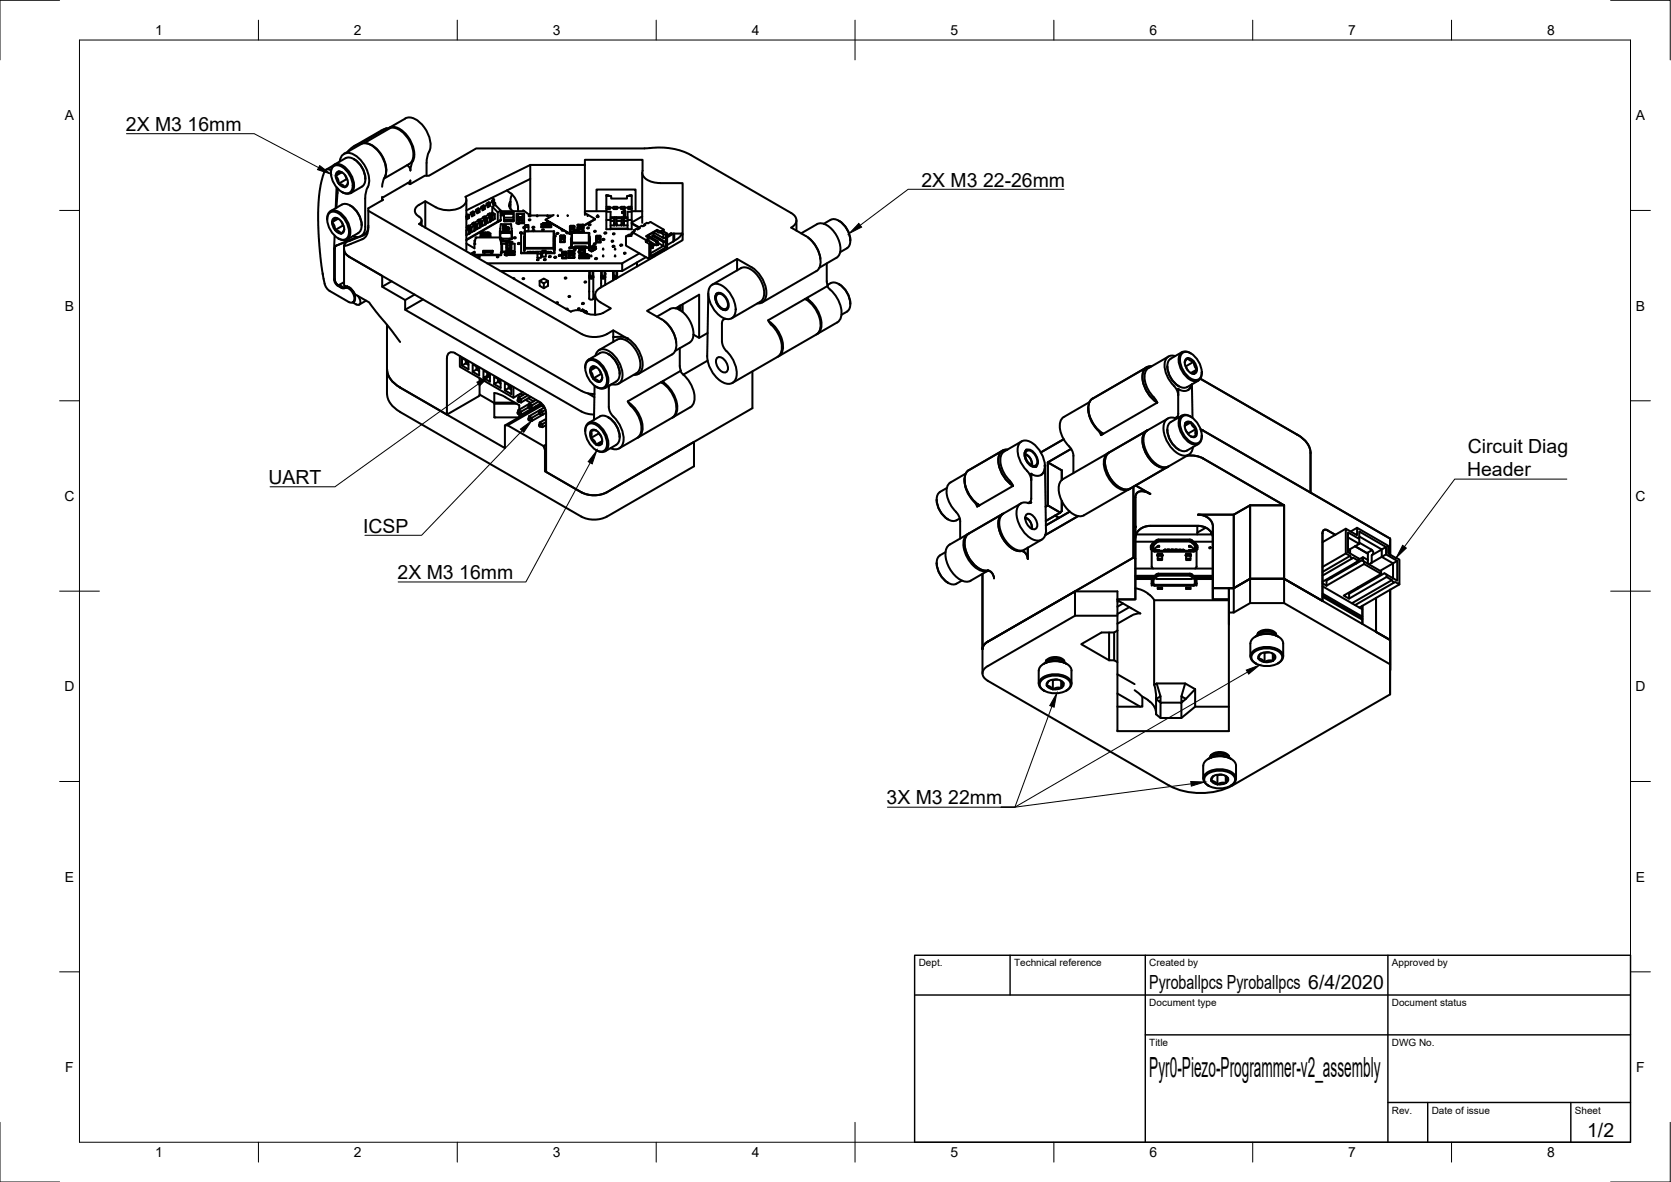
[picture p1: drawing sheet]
<svg xmlns="http://www.w3.org/2000/svg" width="420mm" height="297mm" viewBox="0 0 420 297" stroke-linecap="round" stroke-linejoin="round" font-family="sans-serif">
<defs><g id="words">
<text font-size="7" x="289" y="270.6">Pyr0-Piezo-Programmer-v2_assembly</text>
<g font-size="4.9">
<text x="31.7" y="32.9">2X M3 16mm</text>
<text x="231.7" y="46.9">2X M3 22-26mm</text>
<text x="369" y="113.9">Circuit Diag</text>
<text x="368.9" y="119.7">Header</text>
<text x="67.5" y="121.6">UART</text>
<text x="91.3" y="133.8">ICSP</text>
<text x="100" y="145.5">2X M3 16mm</text>
<text x="222.9" y="202.1">3X M3 22mm</text>
<text x="289" y="248.5">Pyroballpcs Pyroballpcs 6/4/2020</text>
<text x="399.1" y="285.7">1/2</text>
</g>
<g font-size="3.5">
<text x="39" y="8.8">1</text>
<text x="89" y="8.8">2</text>
<text x="139" y="8.8">3</text>
<text x="189" y="8.8">4</text>
<text x="239" y="8.8">5</text>
<text x="289" y="8.8">6</text>
<text x="339" y="8.8">7</text>
<text x="389" y="8.8">8</text>
<text x="16.3" y="30.2">A</text>
<text x="411.3" y="30.2">A</text>
<text x="16.3" y="78">B</text>
<text x="411.3" y="78">B</text>
<text x="16.2" y="125.9">C</text>
<text x="411.2" y="125.9">C</text>
<text x="16.2" y="173.7">D</text>
<text x="411.2" y="173.7">D</text>
<text x="16.3" y="221.6">E</text>
<text x="411.3" y="221.6">E</text>
<text x="16.4" y="269.4">F</text>
<text x="411.4" y="269.4">F</text>
<text x="39" y="290.8">1</text>
<text x="89" y="290.8">2</text>
<text x="139" y="290.8">3</text>
<text x="189" y="290.8">4</text>
<text x="239" y="290.8">5</text>
<text x="289" y="290.8">6</text>
<text x="339" y="290.8">7</text>
<text x="389" y="290.8">8</text>
</g>
<g font-size="2.5">
<text x="231" y="242.9">Dept.</text>
<text x="255" y="242.9">Technical reference</text>
<text x="289" y="242.9">Created by</text>
<text x="350" y="242.9">Approved by</text>
<text x="289" y="252.8">Document type</text>
<text x="350" y="252.8">Document status</text>
<text x="289" y="262.9">Title</text>
<text x="350" y="262.9">DWG No.</text>
<text x="350" y="279.9">Rev.</text>
<text x="360" y="279.9">Date of issue</text>
<text x="396" y="279.9">Sheet</text>
</g>
</g></defs>
<!-- layer: Visible -->
<g fill="none" stroke="#000" stroke-width=".51">
<path d="M86.9 39.8l-2.8 1.6M86.9 39.8a2.79 2.79 0 0 1 3.2 1 5.5 5.5 0 0 1 1.6 5.3l-.7 .8-2.8 1.6M88.9 40l.2 .1M89 36.7l7-4 1.2-.5-6.8 4-1.4 .5-1.6 1.5M90.7 36.2l-4.2 2.5M90.7 36.2a3.2 3.2 0 0 1 3.6 1 7.8 7.8 0 0 1 2.7 6.8l-.3 .6M91 36.1l-.6 .1M91.9 36a6.7 6.7 0 0 1 5.1 5.4l.1 1.9-.3 1.1M97.2 32.2l1-.1-6.7 3.9M97.7 32.2a3.1 3.1 0 0 1 3.7 .8 7.8 7.8 0 0 1 2.7 6.9l-.6 1.4-.3 1.6-.3-.9-.6-.5M98.2 32.1a5.3 5.3 0 0 1 4.9 3.6 5.1 5.1 0 0 1 .2 5.1l-.4 .4M101.9 29.8l-4.1 2.3"/>
<path d="M101.9 29.8a3.2 3.2 0 0 1 3.6 .9 7.8 7.8 0 0 1 2.6 6.8l-.7 1.9-.1 1.5M162.1 37.3h-42.4l-11.8 6.9h-1.1l-3.7 2.1-.6-.3M162.1 37.3h.3a19.1 19.1 0 0 1 11.3 1.7l25.2 14.5a1.93 1.93 0 0 1 1.4 1.9 1.93 1.93 0 0 1-1.4 1.8l3.7 2.1M82.3 55.1a1.82 1.82 0 0 1 .7-2 1.82 1.82 0 0 1 2.2 .2 5.7 5.7 0 0 1 2.6 6.3 1.71 1.71 0 0 1-2.6 .4M82.9 53.5a2.46 2.46 0 0 1 3.2 .9 5.1 5.1 0 0 1 1.4 5.1 1.87 1.87 0 0 1-3 0 5.4 5.4 0 0 1-1.9-5.6zM83.2 43.3v.2M83.2 43.3a1.78 1.78 0 0 1 .9-1.9 1.78 1.78 0 0 1 2 .2 5.7 5.7 0 0 1 2.6 6.3 1.9 1.9 0 0 1-2.8 .3M83.2 42.8l-.5-.2h-.7a11.2 11.2 0 0 0-1.7 5.8l-.3 5.1 .1 5.2 .4 5.7 .8 5.2a4.3 4.3 0 0 0 1.6 3.5l4.8 2.8M83.5 55.8a1.06 1.06 0 0 1 .8-1.1 1.06 1.06 0 0 1 1.2 .6 2.81 2.81 0 0 1 .8 3.1 1.34 1.34 0 0 1-2.1-.6M83.5 55.8l.1 .8 .6 1.2M83.8 41.6l-1.8 1.1M83.8 41.8a2.46 2.46 0 0 1 3.2 1 5.1 5.1 0 0 1 1.4 5.1 1.87 1.87 0 0 1-3-.1 5.4 5.4 0 0 1-1.9-5.6z"/>
<path d="M84.1 59.2l-.1 3.3M84.4 44.2a1.06 1.06 0 0 1 .8-1.1 1.06 1.06 0 0 1 1.2 .5 2.81 2.81 0 0 1 .9 3.1l-.6 .3M84.4 44.2l.1 .8 .7 1.2M84.6 47.1l-.2 5.2M84.7 48.4l.2 .1M84.9 47.4l-.3 4.8M85 55l-1.5 .8M85 59.9l.2 .1M85.1 55l-.3-.1a.49 .49 0 0 0-.5-.1 .49 .49 0 0 0-.3 .5l-.1 .1a.48 .48 0 0 0-.4 .4 .48 .48 0 0 0 .4 .5l.3 1.5M85.2 46.2l.9 .7 .6 .1M85.2 46.2l1 .3 .5 .5M85.4 40.6a2.2 2.2 0 0 1 1.3-2.1 2.2 2.2 0 0 1 2.4 .4 7.8 7.8 0 0 1 3.6 7.6l-.6 1.3-.2 1.5-.1 7.7"/>
<path d="M85.9 55.8l.5 1M85.9 43.3l-1.5 .9M86 51.4l-2.9 1.7M86 51.4a2.79 2.79 0 0 1 3.1 1.1 5.5 5.5 0 0 1 1.6 5.3l-.6 .8M86 43.4l-.8-.3-.4 .6a.48 .48 0 0 0-.3 .5 .48 .48 0 0 0 .3 .5l.4 1.5M86.2 56.7l-2 1.1M86.6 57.6l-.4 .7a.35 .35 0 0 1-.3 .4 .35 .35 0 0 1-.4-.3l-1.3-.6M86.8 44.1l.5 1M87.2 45l-2 1.2M87.5 46l-.8 1M88 51.6a5.8 5.8 0 0 1 2.9 5.1M89.1 40.1a6.1 6.1 0 0 1 2.8 4.9"/>
<path d="M89.9 59.6l-5.4 2.1-.3 .4v8.1l.1 .7a2.96 2.96 0 0 0 2 1.5l.4-.1M90.1 58.6l-2.9 1.6M91.8 57a2.16 2.16 0 0 1-.8 2.1 2.16 2.16 0 0 1-2.3 .2M92 58.6l-1.2 .8M92.6 53l53.7 31M96.1 50.1l.2 .1-3.7 2.2v4.9a2.85 2.85 0 0 1-1.5 2.8l-3.5 1.5-1.1 .2 .7-1.1 4.1-1.5a2.5 2.5 0 0 0 1.3-2.6M96.1 49.5v.9M96.7 44.6l-.5 1.3-.1 1M102.9 41.2l-6.3 3.7M103.2 46.3v-.9l-.2 .3-6.9 4M106 55.4v1.3M106.9 50.6v6.6"/>
<path d="M107.3 41v3.2M109.6 52.1l-2.7-1.5a3.6 3.6 0 0 0-2.6 2.1 2 2 0 0 0 1.4 2 .93 .93 0 0 1-.3 1.6l38.1 22a3.7 3.7 0 0 1 3.9 .4 5.9 5.9 0 0 0 6.2-1.2l-2.6-1.5M117.3 54.4v.1M117.3 57.2l.2-.1 .4 .3-.6 .5M117.3 50.3v12.5M117.3 57.9v1.2M117.4 56.9l.2 .2M117.5 57.1l.3-.4 .4 1v1M117.6 57.1h.1M117.6 53.9v.7l-.3 .2M117.6 54.6l.3 .2M117.9 56.8l.9-.5 .4 .3-.6 .5-.6-.2"/>
<path d="M117.9 58.7l-.6 .4M117.9 57.5v1.4M117.9 54.1v.7l-.6 .4v-.8M118.4 57.1v1.2M118.6 57.1v1.2M118.8 56.3l.3-.4 .2 .3 .3 .7v1M118.8 56.1l.1 .3M118.9 53.1v.8l-.3 .1M118.9 53.9l.4 .1M118.9 56.4h.1M119.2 56l.9-.5 .5 .4-.7 .5-.6-.2M119.2 58l-.6 .3h-.4"/>
<path d="M119.2 56.8v1.3M119.3 53.3v.7l-.7 .4v-.7M119.7 56.4v1.2M119.9 56.4v1.2M120.1 55.4l.2 .2M120.3 52.4v.7l-.3 .2M120.3 53.1l.3 .2M120.3 55.6h.1M120.5 55.3l.9-.6 .5 .4-.6 .5-.7-.2M120.6 57.2l-.7 .4-.3-.1M120.6 56l-.1 1.3M120.6 52.5v.8l-.6 .3v-.7"/>
<path d="M120.6 55.4l-.2-.2-.3 .3M120.6 55.4l.3 1M120.8 59.4h2.5M120.9 56.4v.7M121 55.6v1.2M121.2 58.7h-.4v.8h2.5v-.8h-.4M121.2 58.9l.4-.1v-.3l-.4-.1v.9M121.3 55.6v1.2M121.3 58.9v.4M121.4 54.6l.2 .2M121.4 54.7l.4-.3 .3 .5 .1 1.5M121.4 58.9h-.1"/>
<path d="M121.4 58.5h.2M121.4 58.9h.2M121.6 58.4h1v.5h-1zM121.6 58.9h1M121.6 54.8v.1M121.6 51.6v.7l-.3 .2M121.6 52.3l.3 .2M121.7 58.6v.1v-.1M121.7 58.7h.1M121.9 58.7h.2zM121.9 54.5l.8-.5 .5 .3-.6 .5-.7-.1M121.9 58.7h.2"/>
<path d="M121.9 58.7h.1M121.9 56.4l-.6 .4h-.4M121.9 55.2v1.4M122 58.6h.1M121.9 51.8v.7l-.6 .4v-.8M122 58.6l-.1 .1M122.1 58.7h.1M122.1 58.6h.2M122.2 58.6h-.1M122.2 58.6h.1M122.2 58.7h.1M122.3 58.7h.2"/>
<path d="M122.3 58.6h.1M122.4 54.8v1.3M122.4 58.6h-.1M122.4 58.6h.1M122.4 58.6v.1M122.4 58.7h-.1M122.4 58.7h.1M122.6 58.5h.1M122.6 58.9h.1M122.6 54.8v1.3M122.7 58.9l.2 .4v-.4h-1.6M122.7 53.8l.4-.2 .2 .3"/>
<path d="M122.7 53.8v.2M122.8 53.8l.1 .3M122.9 50.8v.8l-.3 .1M122.9 51.6l.3 .1M122.9 54.1h.1M122.9 58.9l-.3-.1v-.3l.3-.1v.9M123.2 53.7l.6-.3 .6 .4-.5 .3-.6-.2M123.2 55.7l-.6 .4-.4-.1M123.2 54.4v1.4M123.2 51v.7l-.6 .4v-.7M123.3 53.9l.3 1M123.5 54.9v.7"/>
<path d="M123.6 49.7l.6 .4-.5 .3 .3 .2-.8 .4-.3-.2-.6 .4 .3 .2-.7 .4-.3-.2-.6 .4 .3 .1-.7 .4-.3-.1-.7 .3 .4 .2-.7 .4-.4-.2-.6 .4 .3 .2-.7 .4-.3-.2-.3 .2M123.7 54.1v1.2M123.8 51.9v1.5M123.9 54.1v1.2M124 50.6v.7l.5-.3-.3-.2-.2 .2M124.2 50.1v.7M124.4 53.8v1.2l-.5 .3-.4-.1M124.5 51v.5M125.1 55.8h.1M125.1 55.7l-7.8 4.5M125.2 53.3l.7-.4v2.5l-.7 .4zM125.7 55.5l-8.4 4.9"/>
<path d="M125.8 59.9h.1M125.8 59.9h2.9M125.8 58l-.1 1.7M125.8 57.5h.1M125.9 53.6l.1 .3zM125.9 52.9l-1.4-1.4-.7 .4 1.4 1.4M125.9 53.1h5.9M125.9 54h.5M125.9 53.6h.2M126 58.3h2.4v.2h-2.4zM126 58.5h2.4M126.1 53.3h.3v.9h-.5"/>
<path d="M126.1 53.1v.8M126.3 60v.7h1.8v-.3h-1.8M126.6 57.5h.2M126.6 57.7h.4v.1l-.2 .1zM126.6 57.4h.4v.1zM126.6 57.3h.4zM126.6 57.1h.4zM126.6 56.9l.4-.1-.1 .1 .1 .1zM126.6 56.7l.4 .1zM126.6 56.8h.4M126.6 58.2h.4M126.6 56.9l.4 .1"/>
<path d="M126.6 58.1v.1M126.7 57.5h.3M126.7 58h.3v.1h-.4zM126.7 57.5h.1M126.7 57.1h.1zM126.7 56.7h.1zM126.7 56.7h.1M126.7 57.3h.1M126.7 56.9h.2zM126.7 53.7h2.4v1h-2.4zM126.7 55.3v.2h.4M126.7 54.7v.6"/>
<path d="M126.7 55.5v.1M126.7 55.3h.3M126.7 57.2h.1M126.8 53.7v-.3h2.4v2.2h-2.4v-.1h2.4M126.8 55.5h.3M126.8 57.7l-.2 .2 .4-.1M126.8 57.7l.2 .1M126.9 56.7h.1zM126.9 56.7h.1M126.9 57.1h.1M126.9 57.6h.1M126.9 56.9h-.2"/>
<path d="M127 55.3l-.2 .1M127 58.1h-.3M127 57.3h-.4M127 56.8l-.1 .1M127 58.1v.1M127.1 55.5v.1M127.1 55.4h.4M127.5 57.6h.3M127.5 55.5h.3zM127.5 55.5h.9v.1M127.5 55.5v.1M127.5 57.3h.4h-.3"/>
<path d="M127.5 57.3l.3 .1-.3 .1h.4M127.5 57.1l.4 .1zM127.5 57.3l.3 .1M127.5 57.6h.4M127.5 47.8l.9 .8M127.5 57.6h.1M127.6 57.6h-.1M127.6 57.3l.3 .1-.3 .1h.3M127.6 55.3h.6M127.6 55.3l.2 .1M127.9 57.6h.1M127.9 57.3h-.3"/>
<path d="M127.9 57.5h.1M128.1 60v.4M128.3 55.3l-.2 .2h.3M128.3 50.7v.3M128.3 50.7a1.54 1.54 0 0 0 .7 2.4M128.4 51.5l-.4 .3M128.4 50.7h-.1M128.4 48.5a5.3 5.3 0 0 1 1.9 4.6M128.4 55.4h.4M128.5 56.4l.1 3.7M128.5 56.4h-2.6l-.1 3.7M128.6 58v2"/>
<path d="M128.6 59.9h.1M128.7 57.5h.1M128.7 55.5h.4zM128.7 55.5h.4M128.7 55.5v.1M128.8 48.9l-.4 1v2.6M128.9 55.3h.2M128.9 55.3l.2 .1M129.1 55.3v.3M129.1 54.7v.6M129.3 59.6l.4 .1-.4 .2zM129.9 56v-2.3h1.9v2.4h-1.9v-.1h1.9"/>
<path d="M130.2 56.1l.2 .2 .2-.2M130.3 55v.5v-.4h1v.2h-.3M130.3 54.5h1.1v-.8h-1.1v1.3h1.1v-.5M130.3 55.3h.3M130.6 55.3v.3M130.6 55.2h.4M130.8 58.4l.5 .1-.5 .1zM131 55.3v.3M131.4 55.5l-.1-.2v.3M131.4 55v.3M131.8 58.7h-.8v5h4.1M131.8 59.5v.4"/>
<path d="M131.8 60v.4M132 56.5h.9v1.6h-.9zM132 57.1h.9M132 57.1l-.5 .1 .5 .1M132 58.1h7.2M133 55.1l.4 .1-.4 .1zM133.3 45v9.2l-1.8-1.4v.3M133.3 41.5v3.5l-16 7.9M133.4 54.1l-.2 .3-.3-.2 .2-.1 5.9 .1M133.9 57l.5 .1-.5 .1zM134 57.8l.4 .1-.4 .1zM135 54.4l.1-.3 .1 .3"/>
<path d="M136.4 57.6l.4 .1-.4 .1zM136.5 56.5h.2l-.1 .4v-.3h1.6M136.5 56.9v-.8h.4v.3h-.2l.2 .2 1.1-.1-.2-.4h.4v.8M136.5 56.3h-.4v.7M136.7 56.1h.2M136.9 56.1h.9v.4h-.9zM136.9 56.2h.1M136.9 56.3h.2M137 56.2l-.1 .1M137 56.3h.1M137.1 56.3h-.2M137.1 56.2l-.2 .1"/>
<path d="M137.1 56.2l-.1 .1M137.1 56.2h-.2M137.1 56.3h.2M137.1 56.3h.1M137.2 56.2l.1 .1M137.2 56.2v.1M137.3 56.3h.1M137.4 56.2h.1M137.4 56.2h.2l-.2 .2zM137.4 56.3h.1M137.6 56.2l-.2 .2M137.6 54.4l.1-.3 .1 .3"/>
<path d="M137.6 56.3h.2M137.6 56.3h.1M137.6 56.2l.2 .1M137.6 56.2v.1M137.8 56.3h.1M137.8 56.1h.2M138.2 56.6v.3M138.2 56.3h.4v.8h-2.5l2.5-.1M138.2 56.5h-.2l.2 .1M139.2 58.1l.1 .1v4.3l-.1-.2zM139.2 54l-2 1.3 6.1 3.5-6.1-3.6M139.3 58.7l.1 5h-2.2"/>
<path d="M139.3 60v.4zM139.3 59.5v.4zM139.4 59.2l.4 .1-.4 .2M140.1 58.6h.3l-.3 .1zM140.2 54.3l.1-.2v.2M141 59.4h.8v.5h-.8zM141 59.9l.2 .1M141 59.4l-.2-.1v1.4M141 59.3h.2M141 60h.1M141.3 59.7h.3M141.3 59.4h.3"/>
<path d="M141.3 59.4h.3zM141.3 59.7h.3zM141.3 59.9h.1M141.3 59.6h.3M141.3 59.7h.1M141.3 59.4h.2M141.3 59.7h.2M141.3 59.8h.3M141.3 59.4l.2 .1zM141.3 59.5l.3 .1zM141.3 59.6h.1M141.4 59.5l.1 .1z"/>
<path d="M141.4 59.5l.1 .1M141.4 57.7l-.1 .3 .4-.1M141.4 59.5h.1M141.4 59.8h.1M141.5 59.8h.1M141.5 59.8l-.2 .1M141.6 59.7h.1M141.7 59.3h.1M141.8 59.3v-.2h-.8l.2 .3 .8-.1v1.6h-1.2v-.2h1.2M141.8 59.9l-.1 .1M141.8 59.3v.1M141.8 60h.1"/>
<path d="M142 59.6v.2M142.6 58.4l-.2 .2 .4-.1M142.7 54.2v-.1l.1 .1M143.5 56.9v-.2h.8l-.2 .3-.8-.1v1.4h1.2l-.8 .3M143.5 57.6l.8 .1v.4M143.5 57.6l.6-.1 .2 .2M143.5 57h.8v.5h-.8zM143.5 57.5l.1 .1M143.5 56.9v.1M143.5 57.6h.1M143.5 57.7v.4M143.5 56.9h.1"/>
<path d="M143.7 60v1.8M143.7 58.6l-.4 .2M143.7 58.6v3.7h.9M143.7 57l.1 .1M143.7 57.2h.4M143.7 57.4h.4M143.7 57.4h.4zM143.7 57.2l.3 .1zM143.7 57.1l.4 .1zM143.7 57l.3 .1M143.7 57.3l.3 .1M143.8 57l.2 .1"/>
<path d="M143.8 57.4l.2 .1zM143.8 57.1l.2 .1zM143.8 57v.1M143.8 57.3h.2zM143.8 58.5v2.5M143.8 57.3h.2M143.8 57.1h.1M144 57.4h.1M144 57.4h-.2M144 57.1v.1M144 57.1l-.2 .1M144 57.3v.1"/>
<path d="M144 57.3h.1M144.1 56.9h.4v1.4M144.3 57.5l-.2 .1M144.3 57.6h.1M144.3 58.1l-1 .6M145.2 58.2h1.5v.1h-1.5zM145.2 57.3v.9M145.2 57.7l-.7 .4M145.2 57.6l-.9 .5M145.2 57.2h.3M145.3 57.2l-.1 .1M145.5 57.2v.1"/>
<path d="M145.5 56.5h.9v.4h-.9zM145.5 57.2h.9v.5h-.9zM145.5 57.7v.6h.9v-.6M145.5 56.9v.3M145.5 56.5h-.3v.8M146.4 56.5h.3M146.4 56.9l.1 .3M146.5 57.2h.2M146.7 57.2v.1M146.7 56.5v.8M146.7 57.3v.9M147.1 53.5l2.5 1.6-2.9 1.7"/>
<path d="M147.1 53.1h5.4M147.1 41.5v12.5M147.7 54.2l.1-.2v.2M147.7 57.2l.4 .1-.4 .1zM148 58.5v2.5l.2 .2v-2.6h-4.5M148.1 56.4l.4 .1-.4 .1zM148.2 60v.3zM148.2 59.5v.5M149.5 58l.3 .1-.3 .1zM149.6 55l-2.9 1.7M150 53.1v-5.5h9.8v5.5M150.1 59.5h.8v.5h-.8z"/>
<path d="M150.1 59.5l-.2-.1v1.4M150.1 59.4h.1M150.2 54.3l-.2 .1 .2 .2 .3-.1-.1-.2M150.3 59.5h.3M150.3 59.5h.3zM150.3 59.7h.3M150.3 59.8h.3zM150.3 60h.1M150.3 59.5h.1M150.3 59.7h.1M150.3 59.9l.3 .1h-.3M150.4 59.7h.1"/>
<path d="M150.4 59.6l.1 .1zM150.4 54.5l-.1-.5-.2 .6M150.5 59.6h.1M150.5 59.9h.1M150.5 59.9l-.2 .1M150.6 59.8h-.3h.3M150.6 59.5h.1M150.6 59.7h.1M150.7 59.4h.2M150.9 59.4v-.2h-.8l.1 .3 .8-.1v1.5h-1.1l1.1-.1M150.9 59.4v.1M152 58.4l.5 .1-.5 .2z"/>
<path d="M152.5 53.2v4.4h5.3M152.5 49.2h1.2v.7h3.9v-.7h1.2v2.8h-.9v.2M152.5 52h.9v.2M152.5 55.3h1M152.5 52.3h.9M153.3 49.2l-.8-.2v3.5M153.5 57.4h4.3M153.5 54.9h1M153.5 54.6h4.3M153.5 55.5h.9M154.2 58.7l.4 .1-.4 .1zM154.3 52.2v-.2h.9v.2"/>
<path d="M154.3 52.3h.9M154.5 56.2l-.1 .4h-.9M154.5 55.1l-.1 1.5M154.5 54.6v2.1M155 54.6v2.1M155 54.9h1.4M155 55.2v.3M156.1 52.2v-.2h.9v.2M156.1 52.3h.9M156.3 55.5v1.1M156.4 55.2l-.1 .3h-1.3v1.1v-.3M156.4 56.3l-.1 .3h-1.3"/>
<path d="M156.4 54.6v2.1M156.4 53.3l.8-.4v1.5h-.4l.1-1-.5 .2zM156.8 55.1l.1 .4h.9M156.8 54.6v2.1M156.8 54.9h1M156.9 55.5v1.1l-.1-.4M156.9 56.6h.9M156.9 52.9l-.5 .4M156.9 52.9h.3M157.8 55.3h1M157.9 52.2h-.9v.3h-.9v-.3h-.9v.3h-.9v-.3h-.9v.3h-.9v.7h1v4.4M157.9 52.2v.3h.9v.7h-1v4.4h1v-4.4"/>
<path d="M157.9 52.3h.9M158 49.2l.4-.2h.4v.2M158.8 58.9l-.7 .1-.7 .4M158.8 56.1l2.2 1.2-1.6 .6M158.8 53.1h2.7M158.8 52v.5M158.8 56.2l1.9 1M159 58.4l-.2 .2v.7l-1.4 .1v2.3l5.8 3.4v-3.8M159.3 58.2l-.3 .1v.4l-.2-.1M159.4 57.9v.3M161.5 54.4l-2.7 1.5M161.5 43.4v12.6"/>
<path d="M161.6 42.9v-2.7h-14.5v1.3h-13.8l-16.2 8a1.98 1.98 0 0 1-1.3 2.7 7.1 7.1 0 0 1-6.2-.1M161.6 42.9a2.61 2.61 0 0 0 2.5 2.9l1.9 .2h5.6v14.4l-20.6 11.9a1.93 1.93 0 0 0-1.4 1.8 1.93 1.93 0 0 0 1.4 1.9M162 56.4l.3 .1-.7 .4-.2-.2-.7 .4v.3M162 56.7v-.3l.6-.4 .3 .1 .7-.3 3.3 1.9v.5l.8 .5v3.8l-.7 .4M162.9 59.6l.3-.2 2.2 1.2M162.9 59.5l2.1 1.3M163.2 59.8l-.2 .6M164.3 59.1l3.1 1.7h-.6l-2.8-1.5M164.9 58l.8 .5 .3-.2M165.2 57.7l-2.7 1.7M166 58.2v.1l.2-.1v.4M166.8 58.9v.9l-2.5-1.4v.7l-.3 .2v.5"/>
<path d="M166.8 59.8h.6v2.4l-3.8 2.2v-3.3l.4 .2M166.9 57.7l-.9 .5-.8-.5-2.8 1.7 .8 .4-.8 .5-3.4-1.9 .7-.4-.3-.1M166.9 58.2l-.7 .4 .6 .3 .9-.2M167.4 58.9v.9M168.8 58.6l-1.1 .6M169.3 58.7l-1.6 1M169.4 58.7l-.1 2M169.5 58.7v1.8l-.2 .2M171.4 58.8l-.5 .7-1.4 1M171.5 58.8l.1 .2M171.5 58.7h-.1M171.6 58.7h-2.8l-1.1 .6"/>
<path d="M200.3 55.4v2.6M201.4 58.6l4-2.3a3.3 3.3 0 0 1 3.8 1.3 6.6 6.6 0 0 1 1.9 6.3l-.8 .9M202.6 59.3a7.8 7.8 0 0 1 3.6 7.6l-.5 .9-.5 .4-13.6 7.8M203.1 59.7a7.8 7.8 0 0 1 3.2 5.4M207.1 56.2l1.7-.9a2.79 2.79 0 0 1 3.2 1 5.5 5.5 0 0 1 1.6 5.3l-.6 .8-1.8 1M210.9 55.5h.2M211.1 55.5a6.1 6.1 0 0 1 2.7 5M81.1 68.7l.1 .3M84 62.6v7.7M84 70.3l.2 .7 .7 .8M84 62.5h.1M84.9 71.8l1.2 .7 .5-.1"/>
<path d="M85.3 71.6l1 .6M86.5 70.9l-1.3 .7M86.5 62.7a2.17 2.17 0 0 0 1.3 1.8M86.5 61.7v9.7l.2 .6h.4a2.75 2.75 0 0 1 2.1 1.9l3.6 2.1 7.8 9.9M86.6 72.4a2.35 2.35 0 0 1 2.5 2.6 .9 .9 0 0 1-.4 1 .9 .9 0 0 1-1-.1M86.8 72.3a2.38 2.38 0 0 1 2.5 2.6l-.4 1 .2-.1-.4 .2 1.2 .6a.96 .96 0 0 0 .5-1.6l-.5-.7M86.9 72h.1M87.3 72l-.7 .4M92.1 75.6l-1.8 1M98.5 70.7l-2.4 1.4M104.2 74l-2.3 1.4M106.4 75.3l-4.5 2.5"/>
<path d="M117.3 61.2l2 1.2M118.4 63.9l.9-.5v.6M118.9 63.6l-.3 .2M119.3 63.5h.1M119.3 62.4l.3-2.7h6.1l.3 1.6v2.7M119.3 64h6.7v.1h-6.7zM119.3 63.2l-1 .6M119.5 60.5h-.2v.7M120.3 64.5l.4 .1-.4 .1zM121.5 63h2.4v.3l-.4 .2h-1.7l-.3-.2zM121.5 63.3v.3M121.8 63.5v.3"/>
<path d="M122.5 66.2h33.9v1.9h-30.6M123.5 63.5v.3M123.9 63.3v.3M125 64.4l.3 .1-.3 .1zM125.8 60l.5 .1M125.9 60.5h.1v.7M126.3 63.2h1M126.9 64h2.5M127.2 64.1l.2 .1 .2-.1M127.3 63.3h-.4v.8h2.5v-.8M127.3 63.5l.4-.1v-.3l-.4-.1v.9M127.4 62.1v.7h.3v-.2"/>
<path d="M127.4 62.1h.2M127.4 63.6v.3M127.4 61.1l-.4 .2M127.4 61.3v.1M127.5 63.1h.2M127.6 62.6l-.2 .1M127.6 62.2l-.1 .1M127.6 61.3l-.1 .1M127.6 61.7l-.1 .1M127.6 61.3h-1.3v2h.6M127.6 61.7v-.9h.7v1.8h-.7h.7M127.6 62.3h-.2v.2h.2"/>
<path d="M127.6 62.6h-.2v.1h.3M127.6 61.8h-.2v.3v-.2M127.6 61.2h-.2v.6M127.6 60.9h-.2v.3v-.2M127.6 61.4h-.2v.3h.2M127.6 61.7l-.2 .1M127.6 62.2l-.2 .1M127.6 61.7v.9M127.7 63.5h1.1l.1 .4v-.3h-1.5M127.7 63h1v.5h-1zM127.7 63.5l-.3 .1M127.7 62.7h.1"/>
<path d="M127.8 63.2v.2l.1-.1-.1-.1M128 63.3l.1-.1v.2zM128.1 63.2h.1M128.1 63.4h.1M128.1 63.2l-.1 .1M128.2 62.7h.1M128.3 63.2l-.1 .1M128.3 63.2l.1 .1M128.3 61.3h1.1v2M128.3 61.8h.2v.3M128.3 62.3h.2v.2h-.2M128.3 62.6h.2v.1h-.3"/>
<path d="M128.3 61.4h.2v.3h-.2M128.3 61.7l.2 .1M128.3 60.9h.2v.9M128.3 62.2l.2 .1M128.4 62.2v.1M128.4 62.6l.1 .1M128.4 61.7v.1M128.4 61.3v.1M128.4 60.9l.1-.1 .4 .1-.3 .1M128.4 63.3h-.4M128.4 63.3l.2-.1-.1 .1M128.4 63.4h.2"/>
<path d="M128.5 61.3v.1M128.5 63.2h-.1M128.5 63.2v.1M128.5 63.2l-.1 .1M128.5 63.3l-.1 .1M128.5 61.9v.2h-.2M128.5 62.1v.7h-.3v-.2M128.5 61v.2h-.2M128.6 60l-.5 .1M128.7 63.1h.1M128.9 69.9h.4v.2M129 63.5l-.3-.1v-.3l.3-.1v.9"/>
<path d="M129 63.3h.4M129 63.2h.4M130.3 61.1l.4 .1-.4 .1zM131 63.5h4.1M131.4 69.9l.4 .1-.4 .1zM131.8 62.2v.8M131.8 60.4v.4M131.8 60.8v.4M131.8 61.3v.4M131.8 61.7v.4M132 62.3v-4.2l-.2 .1v5.3M132.7 63.4v.1"/>
<path d="M133.2 63.4h-.5l.5 .1M133.5 63.4v.1M133.9 63.4h-.4l.4 .1M134.2 63.4v.1M134.7 63.4h-.5l.5 .1M135 63.4v.1M135.1 65.2l.4 .1-.4 .1zM135.1 63.3h.9v1.5h-.9zM135.1 63.4h-.1h.1M135.1 63.8h.9M135.7 70.6l1-.6 1.1 .6-1.1 .6zM135.7 70.6v1.2l1 .6 1.1-.6v-1.2"/>
<path d="M136 63.5h.4M136 63.7h.4M136.2 63.4h-.2l.2 .1M136.4 63.5h.8v1h-.8v-1.5h.8v.5M136.7 71.2v1.2M136.8 65.1l.5 .1-.5 .1zM137.2 63.5h2.2M137.7 63.4h-.5l.5 .1M138 63.4v.1M138.1 64.4l.4 .1-.4 .1zM138.5 63.4h-.5l.5 .1M139.2 62.3h-7.2l-.2 .2h7.5v1"/>
<path d="M139.3 62.2v.3zM139.3 61.7v.4zM139.3 61.3v.4zM139.3 60.8v.4zM139.3 60.4v.4zM139.3 62.6v.4zM139.4 64.5l.5 .1-.5 .2zM139.9 76l.4 .1-.4 .1zM140.6 64.1l.4 .1-.4 .1zM140.8 62.7l.4 .1-.4 .1zM141 60.5v-.4h.8v.4M141 60.1l.2-.2h.5l.1 .2"/>
<path d="M141.5 63.4v-.2h.8l-.1 .2h-.9v1.4h1.2v.1h-1.2v-.1M141.5 64.1l.8 .1v.4M141.5 64.1l.7-.1 .1 .2M141.5 63.4h.8v.6h-.8zM141.5 64l.1 .1M141.5 63.4h.1M141.5 64.1h.1M141.5 64.2v.4M141.8 63.9h.3M141.8 63.9h.3zM141.8 63.7l.3 .1zM141.8 63.6l.3 .1z"/>
<path d="M141.8 63.5h.1M141.8 63.8h.2M141.8 63.7v.1M141.8 63.9h.1M141.8 63.9h.2zM141.8 63.6l.2 .1zM141.8 63.8h.2zM141.9 63.5h-.1M141.9 63.5v.1M141.9 63.5l.2 .1zM141.9 63.5l.2 .1M141.9 63.8h.2"/>
<path d="M142 63.6l-.2 .1M142 63.9h.1M142 63.9h-.2M142.1 69.8l.3 .1-.3 .1zM142.1 63.9h.1M142.2 63.4h.3v1.4M142.3 64l-.1 .1M142.3 64.1h.1M142.4 77.6h.3l-.1 .2M142.9 64.7h1.5v.1h-1.5zM142.9 63v.8M142.9 63.8v.9"/>
<path d="M143 63h.2M143 63h-.1M143 63.7l-.1 .1M143 74.4l.4 .1-.4 .1zM143.2 62.2h.4l-.4 .1zM143.2 63h.1M143.2 63h.9v.5h-.9zM143.2 63.7h.9v.5h-.9zM143.2 63.5l.1 .3-.3-.1M143.2 64.2v.6h.9v-.6M143.7 62.2h.9M143.7 60l-.2 .2 .2 .1"/>
<path d="M144.1 63.5v.2M144.2 63.7h.2M144.2 63h.2M144.2 63.7l-.1 .1M144.3 62.6l.5 .1-.5 .1zM144.4 63v.8M144.4 63.7l.1 .1M144.4 63.8v.9M144.4 64.7h.1M144.6 62h.4v.3h-.4v-.3h.4M145 62.3h.3M145 62.2h.3"/>
<path d="M145.3 62h.5v.3h-.5v-.3h.5M145.4 77.5l.4 .1-.4 .1zM145.6 63.4h1.5v.1h-1.5zM145.6 63.4h.1M145.6 63.1l-.2 .2 .2 .1M145.6 62.4v1M145.8 62.3h.3M145.8 62.2h.3M145.9 62.4l-.3 .1M145.9 62.4h.9v.5h-.9zM145.9 62.9v.6h.9v-.6M146 64.3h.2l-.1 .4v-.3h1.6"/>
<path d="M146 63.8l.4 .1v.3h-.2l.2 .2 1.1-.1-.1-.4 .3-.1v.9M146 63.8v.9M146 64.1h-.4v.7M146 63.9l-.1 .2M146.1 62h.4v.3h-.4v-.3h.4M146.2 63.9h.2M146.3 78.1l.4-.2 .6 .4-.3 .2 .5-.1M146.4 63.8h1v.5h-1zM146.4 76.1l.5 .2-.5 .1zM146.4 64h.1M146.4 64h.2l-.2 .1M146.4 64.1h.2"/>
<path d="M146.5 77.8h.1M146.5 62.3h.3M146.5 62.2h.3M146.6 64.1h-.2M146.6 64l-.1 .1M146.6 64l-.1 .1h.1M146.6 64h-.2M146.7 64.1h.2M146.7 64.1h.1M146.7 77.9l-.2-.1-.5 .3M146.7 77.9h.1M146.7 64l.1 .1"/>
<path d="M146.7 64v.1M146.8 62h.5v.3h-.5v-.3h.5M146.8 62.4l.3 .1v.9M146.9 64.1h.1M146.9 64v.1M146.9 64h.2l-.2 .2zM147 64.1h.1M147 70.8l.4 .1-.4 .1zM147.1 64l-.2 .2M147.1 62.4v.1M147.1 64.1h.2M147.1 64.1h.1"/>
<path d="M147.2 64l.1 .1M147.2 64v.1M147.3 62.2h.9M147.3 64.1h.1M147.3 78.3h.1M147.4 63.9h.1M147.5 78.4v.4M147.5 78.4h.1M147.7 64.4v.3M147.7 64.1h.4v.8h-2.5v-.1h2.5M147.7 64.3h-.2l.2 .1M148 61h-4.2l-.1 .2h4.5v1h-.9"/>
<path d="M148.1 69.6l.6 .3 .5-.3M148.2 73.2v.1M148.2 74.9a.53 .53 0 0 0 .5 .4 .53 .53 0 0 0 .5-.3M148.2 69.7a.52 .52 0 0 0 .5 .4 .52 .52 0 0 0 .5-.4M148.2 61.8v-.6v1.5M148.2 60.8v.4zM148.2 60.4v.4zM148.2 60.3v.1M148.2 61.2h.1M148.2 69.3a.47 .47 0 0 0 .5 .3 .47 .47 0 0 0 .4-.3M148.2 69.2a.44 .44 0 0 0 .5 .5 .44 .44 0 0 0 .4-.5M148.3 68.1l.1 1.3h.4l.2-.1"/>
<path d="M148.3 69.1a.4 .4 0 0 0 .4 .5 .4 .4 0 0 0 .4-.4l-.1-.1M148.3 68.2l-.1-.1-.1 7M148.4 62.2l-1.1 .1M148.4 62.1l.6-.3 .6 .3-.7 .4zM148.4 62.2l.5 .3M148.4 62.1v.1M148.6 64.4l.1-.3 .1 .3M148.7 63.1l1.1-.6-1.1 .7zM148.7 63.1l-.5-.4 .5 .5M149 62.5h.1M149 68.1v1.2M149 68.2l.2-.1v7"/>
<path d="M149.2 73.2v.1M149.2 61.7l-.2 .1M149.2 61.6h.1M149.2 61.7l.6 .3M149.4 61.2l.4 .1-.4 .1zM149.6 62.1v.6l-.7 .4v-.6M149.6 74.1v5M149.7 64.9l.5 .1-.5 .1zM149.8 62v.5M149.8 62h.1M150.1 60.6v-.4h.8v.4M150.1 60.2l.1-.2h.5l.2 .2"/>
<path d="M150.1 60l.1 .1M150.1 60.1h.1M150.9 60l-.2 .1M150.9 60.1h.1M151.2 69.6l.5 .3 .5-.3M151.2 71.2h.1M151.2 69.7a.52 .52 0 0 0 .5 .4 .52 .52 0 0 0 .5-.4M151.2 69.3a.47 .47 0 0 0 .5 .3 .47 .47 0 0 0 .4-.3M151.2 69.2a.44 .44 0 0 0 .5 .5 .44 .44 0 0 0 .4-.5M151.3 68.1v1.2l.4 .2 .3-.2v-1.2M151.3 69.1a.4 .4 0 0 0 .4 .5 .4 .4 0 0 0 .4-.4l-.1-.1M151.3 68.2l-.1-.1v4.1"/>
<path d="M151.5 60.1l.5 .1-.5 .1zM151.6 64.4l.1-.3v.3M151.6 62.7l.1-.3v.3M152 68.2l.2-.1v3.5M152.2 68.7v.2M153.8 60.5l.4 .1-.4 .1zM154.1 61.8l.4 .1-.4 .1zM154.1 68.1v2.3M154.2 69.6l.5 .3 .5-.3M154.2 69.7l.2 .3h.6M154.2 68.1l.1 .1M154.2 69.3a.47 .47 0 0 0 .5 .3 .47 .47 0 0 0 .4-.3"/>
<path d="M154.2 69.2a.44 .44 0 0 0 .5 .5 .44 .44 0 0 0 .4-.5M154.3 68.1v1.2l.4 .2 .3-.2v-1.2M154.3 69.1a.4 .4 0 0 0 .4 .5 .4 .4 0 0 0 .4-.4l-.1-.1M154.6 64.4l.1-.3v.3M154.6 62.7l.1-.3v.3M155.2 68.1l-.2 .1M155.2 68.1v1.8M155.2 69.7l-.1 .2M156 61.5l.5 .1-.5 .1zM157 63.5l.3 .1-.3 .1zM160.2 65.9v1M160.8 63.7l-4.4 2.5"/>
<path d="M162.4 60.8l.6-.4 .6 .3v.4l-.4 .2zM162.4 60.3v.5M162.4 64.6l-6 3.5M163.6 61.1l.9 .5-.3 .3M163.6 60.8l1.4 .8M163.6 62.3l.1 .1M163.6 61.5h.1M163.7 61.5l.4 .3v.5l-.4 .1zM163.7 61.5l.3-.2 .1 1M164 64.6l3-1.7v-.3l-3 1.7v.4l-.8 .4M164.2 61.7l-.1 .1M164.4 64.3l.2 .1"/>
<path d="M165 60.8l.4 .2v.6h-.4zM165 60.8l.4-.2v1M165.5 61.1l1.3 .7-3.2 1.9M165.5 60.9l-.1 .1M166.8 60.8v1l.6 .4M166.9 62.7l-2.9 1.7M168.5 77.7l-3.3 1.9M168.5 77.6a3.3 3.3 0 0 1 3.7 1.3 6.6 6.6 0 0 1 1.9 6.3l-.7 .9-3.6 2.1M169.3 60.7l-1.6 .9M169.9 77.5l5.9-3.4v10.8l-1.4-.8M170.6 77v.8M171 78v-1.2v1.2"/>
<path d="M171 76.8v1.2M171.6 76.5v1.9M178.1 73.8l-.3 15.6a7.8 7.8 0 0 0 4.7 7 2.13 2.13 0 0 0 2.8-2.4 8.2 8.2 0 0 0-2.6-5.8M178.7 71.9a2.47 2.47 0 0 1 3.4 .3 6.9 6.9 0 0 1 2.6 6.9 2.03 2.03 0 0 1-3.2 .6 7.4 7.4 0 0 1-3.3-6.7zM179.1 71.6l7.2-4.2a3.3 3.3 0 0 1 3.7 1.3 6.6 6.6 0 0 1 1.9 6.3l-.7 .8-7.2 4.2M180.1 73.9a1.5 1.5 0 0 1 2.3 .7l.3 .5a2.12 2.12 0 0 1 0 2.7 2.12 2.12 0 0 1-2.4-1.4 2.69 2.69 0 0 1-.2-2.5zM180.3 74a1.73 1.73 0 0 1 2.3 1.1 1.73 1.73 0 0 1-.2 2.6 2.63 2.63 0 0 1-2.1-3.7zM180.3 73.7a2.12 2.12 0 0 0 0 2.7 2.12 2.12 0 0 0 2.4 1.4M185.3 65.1v2.9M189 67.2l-3.7-2.1-22.6 13 3.6 2.1M189 67.2a7.7 7.7 0 0 1 3.5 7.6 1.94 1.94 0 0 1-2 1.4M202.4 75.1a7.8 7.8 0 0 1 3.8 7.7l-.5 .9-.5 .4"/>
<path d="M203 74.8l.7 .9M203.7 75.7a7.4 7.4 0 0 1 2.6 7.2l-.9 1.1M207.9 66.2v4.4M207.9 70.6l.3 1.2M208 71.9l.4 .5a7.9 7.9 0 0 1 3 7.5l-.9 1.1-5 2.9M208.1 71.6a2.6 2.6 0 0 1 3.9 .7 5.5 5.5 0 0 1 1.6 5.3l-.6 .7-1.4 .8M208.2 71.8l-15.1 8.7 .9 1.2M210.3 64.8l-4.3 2.5M210.9 71.4l.2 .1M211.1 71.5a6.1 6.1 0 0 1 2.7 4.9M97.3 81.6v17.3a5.6 5.6 0 0 0 3.3 4.6M97.3 92.8a5.6 5.6 0 0 0 3.3 4.6"/>
<path d="M114.5 88.8l21.2 12.2 .8 .7 .6 1 .2 1.1v14.8l8.9 5.1M114.5 88.8a1.29 1.29 0 0 0-1.5-.2 1.29 1.29 0 0 0-.6 1.4v14.2l8.2-4.8v-4.4M115.6 89.5v2.7l13.5 7.8 2.4-1.4M117.1 90.5v.8l.7-.4M117.8 90.9l-1.6-.9v1.9l.9-.6 .7 .4M117.8 90.9v1.9l-1.6-.9M119.8 92.1v.8l.7-.4M120.5 92.5l-1.6-1v1.9l.9-.5 .7 .4M120.5 92.5v1.9l-1.6-1M120.6 99.2l3.7 2.1M122.5 93.6v.8l.7-.4M123.2 94l-1.6-.9v1.9l.9-.6 .7 .4"/>
<path d="M123.2 94v1.9l-1.6-.9M125.2 95.2v.8l.7-.4M125.9 95.6l-1.7-1v1.9l1-.5 .7 .4M125.9 95.6v1.9l-1.7-1M127.9 96.8v.7l.7-.4M128.6 97.1l-1.7-.9v1.9l1-.6 .7 .4M128.6 97.1v1.9l-1.7-.9M129.1 97.2v2.8M130.2 99.3l.6 .4M130.3 100l-.2 .6 .3 .1 .6-.3v.7M130.9 98.9l.6 .4M132.1 98.9l-1.8 1.1"/>
<path d="M132.8 99.3l-1.8 1.1-.7-.4M133.4 99.7l-2.4 1.4M146.3 98.3l-58.5-33.8 8.3 4.8v2.8l5.8 3.3v2.4l44.3 25.6 1.5 .6 1.7 .2M146.3 83.9a7 7 0 0 0 6.3 0M146.3 98.3l1.4 .5 1.8 .2M147.2 92.5a1.82 1.82 0 0 1 .7-2.1 1.82 1.82 0 0 1 2.2 .2 5.7 5.7 0 0 1 2.6 6.3 1.87 1.87 0 0 1-2.8 .3M147.7 90.8a2.46 2.46 0 0 1 3.3 .9 5.1 5.1 0 0 1 1.4 5.1 1.87 1.87 0 0 1-3.1 0 5.4 5.4 0 0 1-1.9-5.6zM147.8 98.9l1.7 .9M148.4 93.1l.1 .8 .6 1.2M148.4 93.1a1.06 1.06 0 0 1 .7-1.1 1.06 1.06 0 0 1 1.3 .6l.7 1.1 .3 1.2M149.5 97l-.1 8.5M149.7 89.4a1.91 1.91 0 0 1 2.9-1.4 7.1 7.1 0 0 1 3.7 7.4 1.82 1.82 0 0 1-2.4 1.1"/>
<path d="M149.9 92.3l-1.5 .9M150 92.3l-.4-.1a.53 .53 0 0 0-.8 .4v.1a.48 .48 0 0 0-.4 .4 .48 .48 0 0 0 .3 .5l.4 1.5M150.6 88l4.5-2.6a3.3 3.3 0 0 1 3.8 1.3 6.6 6.6 0 0 1 1.9 6.2l-.8 .9M150.8 93.1l.5 1M150.8 88.7l-2.8 1.7M150.8 88.7a2.79 2.79 0 0 1 3.2 1.1 5.5 5.5 0 0 1 1.6 5.3l-.6 .7-2.9 1.7M151.1 94l-2 1.1M151.4 94.9l-.3 .7a.35 .35 0 0 1-.3 .4 .35 .35 0 0 1-.4-.3l-1.3-.6M151.4 94.9a1.06 1.06 0 0 1-.8 1.1 1.06 1.06 0 0 1-1.2-.6l-.3-.3M152.6 84l1.6-1 3.7 2.1M152.9 88.9a5.9 5.9 0 0 1 2.9 5.1M153.5 96.7l-.4 .8v4.8l.5 1.6a9.2 9.2 0 0 1 3.2 6.8 2.15 2.15 0 0 1-3.3 1.9"/>
<path d="M154.1 96.6l-.5 .1M154.2 84.7l2.3-.1 1.4 .5M154.2 83v1.7M154.2 84.7v1.2M157.9 85.1a7.7 7.7 0 0 1 3.5 7.7 1.94 1.94 0 0 1-2.1 1.4M160 93.8l-4.5 2.6M166.2 96.1l.1 .1M166.3 80.2a7.8 7.8 0 0 1 3.6 7.6l-.5 .9-.4 .4-8.5 4.9M166.4 96.1a7.8 7.8 0 0 1 3.5 7.6l-.5 1-.4 .3-8.5 4.9M166.7 95.7l.8 .9M166.9 80.6a7.8 7.8 0 0 1 3.1 5.4M167.5 96.6a7.4 7.4 0 0 1 2.6 7.2l-1 1.1"/>
<path d="M170.9 87.5v4.5l.3 1.1-13.4 7.8M171.1 93.2l.7 .9M174.4 84.1h.1M177.9 90.6l-6.1 3.5a7.6 7.6 0 0 1 2.6 7.1l-.8 1.2-4.4 2.5M177.9 83.7l-2.1 1.2M180.3 89.9a1.73 1.73 0 0 1 2.3 1.2 1.73 1.73 0 0 1-.2 2.5 2.63 2.63 0 0 1-2.1-3.7zM182.6 80.2l-.7 .1-.3 .6v4.9l.3 1.3 .8 1.1M189.2 93.3v9.3l-36.6 21.1M193.3 80.7a7.7 7.7 0 0 1 3.4 7.7l-.6 .9-.4 .3M194 81.7a7.5 7.5 0 0 1 2.4 6.9l-.9 1.1-11.4 6.5M205.2 84.1l-9.4 5.4M288.3 92.3l-13.6 7.9"/>
<path d="M288.8 92.5a3.7 3.7 0 0 0-.5 4.5l1 1.8 .9 1.1M289.5 92.1a2.21 2.21 0 0 0-2.3 2.7 8.2 8.2 0 0 0 3.8 6.4M290.1 99.9l.9 1.3-14.2 8.2-.8-1.4M293.5 92a6.2 6.2 0 0 0 2.9 5.1M293.8 89.6l-5 2.9M295.1 97l.9 1.1 .2 1.2M295.5 89.5a1.96 1.96 0 0 0-2.7 2.1 7.6 7.6 0 0 0 2.4 5.4M297.2 88.5l-2.8 1.6a2.79 2.79 0 0 0-.7 3.3 5.5 5.5 0 0 0 3.8 4l1-.1M297.3 88.7a2.46 2.46 0 0 1 3.2 1 5.1 5.1 0 0 1 1.4 5.1 1.87 1.87 0 0 1-3-.1 5.4 5.4 0 0 1-1.9-5.6zM297.9 91.1a2.92 2.92 0 0 0 2.3 2.8 .95 .95 0 0 0 .8-1.1M297.9 91.1a1.06 1.06 0 0 1 .8-1.1 1.06 1.06 0 0 1 1.2 .5l.8 1.1 .3 1.2M297.9 91.1l.3-.6a.33 .33 0 0 1 .3-.4 .33 .33 0 0 1 .4 .2l.6 .4a.65 .65 0 0 1 .7 .9l.3 .7a.6 .6 0 0 1 .4 .6 .6 .6 0 0 1-.5 .6l-.2 .2a.28 .28 0 0 1-.2 .3 .28 .28 0 0 1-.3-.2l-.4-.1"/>
<path d="M298 92l.5 .9M298.7 98l.6-.5 .3-.9a2.02 2.02 0 0 1-3.4 1.2l.1 6.1-.3 .9M299.4 88.8a1.8 1.8 0 0 0-2.1-.3 1.8 1.8 0 0 0-.9 1.9 5.7 5.7 0 0 0 4.1 5.4 1.71 1.71 0 0 0 1.7-2M299.7 96.6l.1 8.4M300.2 90.9l-2 1.1M300.9 92.9l-1.5 .8M301.3 95.7l-2.8 1.6M301.8 95.2l24.4 14.1a5.6 5.6 0 0 1 3.3 4.5v10M302.2 93.6v.2M100.6 103.5l45.6 26.3M112.4 104.2l-11.8-6.8 26.4 15.2v-5.7M124.3 101.2h5.1"/>
<path d="M124.3 101.5h5.6M127.6 106.9l9.1 5.2M130.1 100.6v.2l.3 .2M130.1 103.7v.3l.3 .1M130.3 103.1l-.2 .6 .3 .1 .6-.4v.9M130.4 100.7v.3l.6 .1M130.4 103.8v.3l.6 .2M130.6 102.9v-1.1l-4-2.3-2.3-.7v6.1h6.2M130.6 104.1v.7M132.1 100.5l1.4 .7M132.8 100.1l1.4 .8M132.8 102.1v.3l.3 .1"/>
<path d="M132.8 102.4l-1.8 1-.7-.3M132.8 105.2v.3l.3 .1M133 101.5l-.2 .6 .3 .2 .6-.4v.8l-.6-.2v-.2M133 104.6l-.2 .6 .3 .2 .6-.4v.8M133 101.5l-2.7 1.6M133.1 105.4v.2l.6 .2M134.8 100.5l-1.8 1M134.8 102l.3 .2M135.4 100.9l-1.7 1-.7-.4M135.5 103.7v.3l.3 .1M135.5 104l-1.8 1-.7-.4M135.5 106.8v.3l.3 .1"/>
<path d="M135.5 101.6l1.4 .8M135.7 103.1l-.2 .6 .3 .1 .6-.4v.9M135.7 106.2l-.2 .6 .3 .1 .6-.3v.7M135.7 103.1l-2.7 1.5M135.8 103.8v.3l.6 .2M135.8 106.9v.3l.6 .1M135.8 101.5l.9 .5M135.9 101.9l-8.9 5h.6l8.5-4.9M136.1 101.3l-5.1 3M136.4 104.3l-2.7 1.5M136.9 102.4l-1.2 .7M137 113.1v5.3"/>
<path d="M137.2 103l-.8 .4-.7-.3M137.3 103.7l-.9 .6M137.3 118.3l-.3 .1 9.2 5.3M137.3 111.7l-.6 .4 .3 1 .3-.1M137.3 106.1l-.9 .5-.7-.4M137.3 105.3l-1.6 .9M137.3 106.8l-.9 .5M147.2 108.4a1.82 1.82 0 0 1 .7-2 1.82 1.82 0 0 1 2.2 .1 5.7 5.7 0 0 1 2.6 6.3 1.87 1.87 0 0 1-2.8 .3M147.7 106.7a2.46 2.46 0 0 1 3.3 .9 5.1 5.1 0 0 1 1.4 5.2 1.87 1.87 0 0 1-3.1-.1 5.4 5.4 0 0 1-1.9-5.6zM148 106.3l2.8-1.7a2.79 2.79 0 0 1 3.2 1.1 5.5 5.5 0 0 1 1.6 5.3l-.6 .8-2.9 1.6M148.6 110.1l-.2-.5a1.09 1.09 0 0 1 .3-1.4 1.09 1.09 0 0 1 1.5 .2 2.9 2.9 0 0 1 1 3.2M148.6 110.1l.7 1.1 .6 .5"/>
<path d="M149.9 108.2h-.7a.34 .34 0 0 0-.5 0 .34 .34 0 0 0 0 .4v.8a.63 .63 0 0 0 .4 1.1l.5 .6a.64 .64 0 0 0 .4 .6 .64 .64 0 0 0 .7-.1h.5M150.6 108.7l.5 1M150.6 108.9l-2 1.2M151.2 111.6a.95 .95 0 0 1-1.3 .1M151.4 110.7l-.2 .9M151.4 110.9l-1.5 .8M152.9 104.8a5.9 5.9 0 0 1 2.9 5.1M157.8 100.9l.9 1.2M158 101.1a7.7 7.7 0 0 1 3.4 7.7l-.6 .9-.4 .3M158.7 102.1a7.5 7.5 0 0 1 2.4 6.9l-.9 1.1M160.2 110.1l-4.5 2.6M242.8 119l-3.8 2.2"/>
<path d="M243.6 118.1a4 4 0 0 0-.5 5l.6 1.3 .9 1.2 1.6 1.4M252.1 113.2l-8.5 5M252.5 113.4a3.7 3.7 0 0 0-.5 4.5l1 1.9 .9 1M253.3 113a2.21 2.21 0 0 0-2.3 2.8 8.2 8.2 0 0 0 3.7 6.3M256.9 110.9l-4.4 2.5M257.8 114.1l.6 .3 .6 .8 .5 1.5M257.8 114.4a1.69 1.69 0 0 1 1.4 2.4M257.8 113.3a1.5 1.5 0 0 1 2.4 .6l.3 .5a2.12 2.12 0 0 1 0 2.8 2.12 2.12 0 0 1-2.4-1.4 2.69 2.69 0 0 1-.3-2.5zM258.1 113.4a1.75 1.75 0 0 1 2.3 1.1 1.75 1.75 0 0 1-.2 2.6 2.67 2.67 0 0 1-2.1-3.7zM258.1 113.1a2.12 2.12 0 0 0 0 2.7 2.12 2.12 0 0 0 2.4 1.4M258.2 118.3l.8 1.1 .3 1.3M262.7 117.1l.3 16a2.33 2.33 0 0 1-1.2 2.6 2.33 2.33 0 0 1-2.8-.5 7.9 7.9 0 0 1-3.3-7.2 2.11 2.11 0 0 1 3.1-1.5l.5-.2"/>
<path d="M262.7 117.1a2.12 2.12 0 0 1-.9 2.3 2.12 2.12 0 0 1-2.5-.3v6.1l-.3 .9M262.7 117.1a2.56 2.56 0 0 1-1 2.3M262.7 117.1a7.2 7.2 0 0 0-4.3-6.3 1.98 1.98 0 0 0-2.5 2.3 7.6 7.6 0 0 0 2.3 5.2M263.5 116.2l3.5 2v2.4M267.4 110.4l-5.7 3.3M268.8 112.2l.8 1.1 .3 .9v4.7M269.3 112.8l-5.8 3.4v10.8M273.6 102.4a7.4 7.4 0 0 0 2.4 5.6M273.9 101.1l-6.4 3.7a3.7 3.7 0 0 0-.6 4.5l1 1.9 1 1M274.7 100.2a4 4 0 0 0-.5 4.9 8.3 8.3 0 0 0 3.2 3.9M277.1 108.9v.3M277.1 108.9l.3 .1"/>
<path d="M278.6 113.9l-11.3 6.5a3.2 3.2 0 0 0-1 3.6 7.1 7.1 0 0 0 5.2 5.7l1-.2M278.8 113.8a3.4 3.4 0 0 0-1 4.2 7.3 7.3 0 0 0 4.8 5.2l1.4-.3M278.9 113.7a3.2 3.2 0 0 0-1 3.5 7.1 7.1 0 0 0 5.2 5.8l1.1-.2 9.4-5.5M288.3 108.3l-9.4 5.4M288.5 108.2a3.4 3.4 0 0 0-1 4.2 7.3 7.3 0 0 0 4.8 5.2l1.4-.3M291 101.2h.1M293.5 108v.2M293.5 108.1a6.2 6.2 0 0 0 2.9 4.9M293.6 105.2l-5 2.9a3.2 3.2 0 0 0-1 3.6 7.1 7.1 0 0 0 5.2 5.7l1.1-.2M296.2 104.9l-.2 .2M296.2 104.9l-.2-.1-.6 .3M296.3 104.9a1.51 1.51 0 0 1-1.6 0 2.14 2.14 0 0 0-2.2 2.4 7.5 7.5 0 0 0 5.1 7.2 2.07 2.07 0 0 0 2.4-2.1"/>
<path d="M297.2 104.4l-2.8 1.7a2.79 2.79 0 0 0-.7 3.2 5.5 5.5 0 0 0 3.8 4.1l1-.2M297.3 104.7a2.46 2.46 0 0 1 3.2 .9 5.1 5.1 0 0 1 1.4 5.1 1.87 1.87 0 0 1-3 0 5.4 5.4 0 0 1-1.9-5.6zM298.1 106.3l-.2 .9M298.1 106.3h.7a.49 .49 0 0 1 .6-.1 .49 .49 0 0 1 .3 .5l.4 .7a.84 .84 0 0 1 .4 1.3l.1 .4a.36 .36 0 0 1 .1 .5 .36 .36 0 0 1-.5 .1h-.8M298.1 106.3a2.92 2.92 0 0 0 1.3 3.4M298.1 106.3a1.29 1.29 0 0 1 2 .3l.7 1.2M298.2 108.2l.6 .9M298.5 114.5l2.5 .1 1.5 .6M298.9 114.3l-5.1 2.9M299.3 104.6l.1 .1M299.3 104.6a1.78 1.78 0 0 0-2.1-.2 1.78 1.78 0 0 0-.8 1.9 5.7 5.7 0 0 0 4.1 5.4 1.85 1.85 0 0 0 1.7-2.2M299.4 106.1l-1.5 .9"/>
<path d="M300.8 107.8l-2 1.1M300.8 107.8l.1 .4a1.06 1.06 0 0 1-.1 1.3 1.06 1.06 0 0 1-1.4 .2M301.3 111.6l-2.8 1.6M301.9 107.9l.6 .3M302.5 108.2l47 27.1v4.1v-4.1M302.5 115.2l20.4 11.8M146.2 123.7a7 7 0 0 0 6.4 0M146.2 129.8a7 7 0 0 0 6.4 0M152.6 123.7l21.9-12.7v6.2l-21.9 12.6M235.5 125.5v.2M235.5 125.7a6.1 6.1 0 0 0 2.8 4.8M237.7 138.8a2.73 2.73 0 0 0-2.1 2 5.9 5.9 0 0 0 3.9 6.1l1-.2 1.4-.8"/>
<path d="M238.1 122.6l-1.7 1a2.79 2.79 0 0 0-.7 3.3 5.5 5.5 0 0 0 3.8 4h.5l1.3-.6M238.3 130.5l.1 .1M239 121.2a3.7 3.7 0 0 0-.5 4.5l.6 1.3 2.1 3 .2 .8v4.5M242.5 120.3a7.4 7.4 0 0 0 2.4 5.7M243.3 134.2l-4.5 2.6a3.2 3.2 0 0 0-1 3.6 7.1 7.1 0 0 0 5.2 5.8l1.1-.3M243.5 134.2a3.3 3.3 0 0 0-1 4 7 7 0 0 0 5.1 5.4l.9-.2-4.4 2.5M245.9 126.8v.4M246 126.8l.3 .2M246.2 127h.1M252.1 129.2l-8.5 4.9a3.4 3.4 0 0 0-.9 3.8 7.3 7.3 0 0 0 5 5.5 1.86 1.86 0 0 1 2.2 1.9M252.2 129.1a3.2 3.2 0 0 0-1 3.8 7.1 7.1 0 0 0 5 5.6 1.84 1.84 0 0 1 2.2 1.9v-2.8M253.9 120.8l.8 1.3-9 5.2-.9-1.3"/>
<path d="M254.7 122.1h.1M256.7 126.5l-4.4 2.5a3.2 3.2 0 0 0-.9 3.6 7.1 7.1 0 0 0 5.1 5.8l1.1-.3M257.8 130.1l.6 .3 .8 .9 .3 1.1v.5M257.8 130.4a1.69 1.69 0 0 1 1.4 2.3M258.1 129.3a1.75 1.75 0 0 1 2.3 1.1 1.75 1.75 0 0 1-.2 2.6 2.67 2.67 0 0 1-2.1-3.7zM259 126.1l-.5 .3M259 126.1l.3 .2M259.3 126.3l-.3 .1M261.9 135.6l-4.3 2.5M262.9 127.3l.6-.3 3.1 1.8M265.3 129.6l1 .5M267 125.9v2.5l-.4 .4-3.6 2.1"/>
<path d="M269 128.6l-6 3.4M271.1 129.7l-8.3 4.8M283.9 123l-11.4 6.5M285 122.3v17.8M285.5 136.1h4.8M285.5 122l3.7 2.1a2.66 2.66 0 0 0-3.4-.1l-.3 1v15.4M285.6 134.3h19.2M289.6 137v5.4M289.6 138a.69 .69 0 0 0 .7 .6h9.8M289.6 137l-.2 .2v.8l.2 .2M289.6 137.4l-.2 .2M289.7 138l.3 .4 .3 .1h9.8"/>
<path d="M289.7 138l.1-1.2 1.2-1 .3-.1h8l1.4 1.1v1.2M290 138.1l.3 .3M290 138.2h1.5v.2M290.3 138.4h9.8M290.9 137.4h.6v-.2h-.4l-1.1 1M290.9 138.2l-.3 .2M291 137.4h.1M291 138.2h.1M291.1 139.6h1.1h-1.1M292.2 139.4h-1.1v-.3h1.1v.6M292.2 139.4l.2 .1-.2 .2v1h-1.1l-.1-1.2 .1-.1v.3M292.7 138.3l.2-.1v.2"/>
<path d="M292.8 138.2h4.8h-.1l.3 .2M292.9 138.2l-.2 .2M292.9 138.2h4.6v.2M296.5 138.2h.4M297.6 138.2l.2 .1M298.2 139.4v.3M298.2 139.6h1.1h-1.1M298.2 139.4l-.1 .1 .1 1.2h1.1v-1l.2-.2-1.3-.1v-.3h1.1v.6M299.4 137.3l1 .9M299.4 136.2l1 .8v1.1M299.4 137.2h-.4v.2h.6M299.4 136.1h-8.2l-1.2 .9v1.1"/>
<path d="M299.5 138.2h.1M299.5 137.4h.1M299.6 138.2l.1 .1M299.7 135.8l1.4 1.4v.8l-.2 .2M299.7 138.3l.1 .1M299.7 135.8l-.5-.2h-8.1l-1.3 1-.2 .4M300.1 136.1h4.9M300.4 138.2h-1.4v.2M300.4 138.1l-.3 .3M300.7 138l-.3 .4-.3 .1M300.9 137v5.4M300.9 137.4l.2 .2"/>
<path d="M300.9 138a.69 .69 0 0 1-.8 .6M301.1 132.2v1.6l2.1-1.2M301.1 133.8v.5M304.1 137.6l.4 .1-.3 .1zM304.6 133.9l.1 .1M304.6 133.9l-1.1-1.1-1.7-.6h-12.6a3.5 3.5 0 0 0-3.7 3M304.7 134l.3 1.2M304.7 134h.1M310.2 129.3v18.5l4.1-2.4h8.6l26.6 15.4v7.6v-7.6l-3.5-2v-8.5M314.3 127v24.6M322.9 127h-8.6l-4.1 2.3h-9a3.5 3.5 0 0 1 3.8 3.1v18.2M322.9 127v24.6"/>
<path d="M335.7 134.4l-1.9-1.1a.79 .79 0 0 0-.9-.1 .79 .79 0 0 0-.4 .8v17l-9.6-5.6h-8.6l-4.1 2.4h-5.2v2.8h4M338.4 139.1l-5.9 3.4M338.4 132.9l-5.9 3.4M338.9 135.1l2.9 1.6-2.9 1.6M339.3 138.1l.2 1M339.5 139.7l-7 4M340.7 137.3l3.2 1.8M341.2 132.6l-1.6 1M341.8 136.4l3 1.7a.79 .79 0 0 1 .5 .6 .79 .79 0 0 1-.4 .8M341.8 134.8l5.6 3.3 1.1-.6M341.8 135.4v1.3M344.7 138.4l-.8 .5v2.8"/>
<path d="M344.9 139.5l2.5-1.4v1.8l-2.5 1.5zM345 138.2l-.2 .2M348.5 139.3l-1.1 .6 2.9 1.7 1-.6M235.5 141.4v.3M235.5 141.6a6.2 6.2 0 0 0 2.9 4.9M247 144.2v25M270.3 148.6v6.1M278.9 158.9v7h1.2M280.1 158.9h-3.1l-5.1 3 7 4M281 150.6h4.5v-10.2l-.5-.3-36.7 21.2M281 158.5l-.9 .4v7l.9 .5M281 158.5v-9.9h-10.7l-22 12.7"/>
<path d="M281 150.8l5.7 3.4M281 154.7h-10.7l-20.4 11.8a4.5 4.5 0 0 0-2.8 2.2 1.94 1.94 0 0 0 1.3 2.4M281.4 151.1h-.4M282.4 151.6l-1.4 .9M284 152.6l-3 1.7M285.5 145.5h4.1M285.5 145h4.5M285.5 144.7h4.8M285.5 142.9h19.5M285.5 147.8l1.7 .5 1.9 1.3M286.7 154.2l-1.8 .3-3.9 2.2M289.2 149.6l1 1.2"/>
<path d="M289.6 146.6a.69 .69 0 0 0 .7 .6M289.6 142.3l.4 .6M289.9 145.2l-.2 1.4 .3 .4 .3 .1h9.8M290.3 147.2h9.8M290.7 145.5h9M290.9 144.4l-1 .9M290.9 144.4l.4-.1h8l.3 .1M291.1 144.7l-1.1 .9v1.1l.2 .2 9.9 .1M291.1 144.7h8.3M291.1 148h.1M291.1 140.4h1.1M291.3 144.2h7.8"/>
<path d="M291.3 144.2l-.5 .1-1.1 1-.1 1.9M292.2 148h-1.1v-.3h1.1v.3M298.2 148h.1M298.2 140.4h1.1M299.2 144.2l.5 .1M299.3 148h-1.1v-.3h1.1v.3M299.4 144.7l1 .9v1.1l-.3 .2M299.6 144.4l.9 .9M299.7 144.3l1 .9 .2 .4M300.1 144.7h4.9M300.5 145h4.5M300.6 145.2l.1 1.4-.3 .4-.3 .1"/>
<path d="M300.9 145.5h4.1M300.9 145.6v1.6M300.9 146.6a.69 .69 0 0 1-.8 .6M300.9 142.3l-.4 .6M309 150.8v32.9h-28v-25.2M309 150.8h-18.8v21.3l.6-.3h7.2l2.5 1.4M309 150.8v-3v9.2M309 147.8h1.2v6.1h-1.2M310.2 153.9l4.1-2.3h8.6l26.6 15.3v7.6l-39.6 22.9a17.6 17.6 0 0 1-15.9 0l-45.7-26.3M315.8 159.9l-.2 .1M315.8 159.9a6 6 0 0 1 5.6 .1M316.1 159.7a2.16 2.16 0 0 1 2.7-1.4l1.4 .3a1.18 1.18 0 0 1 .7 1.1"/>
<path d="M316.3 159.2v.3M316.4 159.6l1-.7 1.4-.2 1.2 .2 .8 .8-.6-.8-1.2-.3-1.5 .2-.7 .3-.4 .5M316.4 158.9l-.1 .8M317.8 159.3l1.2-.1 .8 .2M317.9 158.7l.8-.2 .7 .2M319.4 159.3h-1.5M320.8 159.2l-.1 .3M332.5 149.2l10.1 5.8M332.5 149.6l10.1 5.8M332.5 150l10.1 5.8M332.5 147.3l10.1 5.8M332.5 146.6l1 .6"/>
<path d="M333.5 147.2l9.5-5.5 4.3 2.5-9.4 5.5 1.3 .7 9.4-5.4 1.4 .8-10.1 5.8M334.6 145l.2 .2M339.9 140.4l-7.4 4.3M341.1 141.3l-.1 .4-.3-.2M341.4 147.6v.4M341.6 141v-.7l-2.7-1.5v-5l2.9 1.6v-1.8l6.7 3.9v1.8l2.8 1.7v4.9l-2.7-1.5v.6M341.6 140.6l1.1-.6 1.2 .7M342.6 152.3v4.5M342.7 140v1M343 141.1v.6M344.9 141.4l-.7 .4M347 143.5l3.3-1.9v3.7"/>
<path d="M347.3 144.2v-.6l-4.9-2.8-8.9 5.1v1.3M348.6 144.4l-.5-.3-8.9 5.1v1.2M349.5 148.2v26.3M350 145.8l.4 .7 .4-.3 1.1 .7v-6.3l-2.9-1.6v-1.9l-7.8-4.5v1.9l-2.8-1.6v6.2l1.1 .6 .4 .7 .4-.2 1.3 .8-9.1 5.2M350.4 146.5l-9.7 5.6M351.1 140.2h-.1M351.9 146.9l-10.1 5.8M248.4 161.3l-.5 .3a1.99 1.99 0 0 0-.9 1.5M261.2 171.8v-3.3a2.79 2.79 0 0 1 2.5-2.2 5.5 5.5 0 0 1 5.4 1.3l.3 .9v3.3M262 170.8a5.4 5.4 0 0 1 7 .5 1.87 1.87 0 0 1-1.5 2.6 5.4 5.4 0 0 1-5.9-1.2 1.45 1.45 0 0 1 .4-1.9zM262.4 166.9a5.9 5.9 0 0 1 5.8 0M262.6 173.6a1.82 1.82 0 0 1-1.4-1.7 1.82 1.82 0 0 1 1.2-1.8 5.7 5.7 0 0 1 6.8 .9 1.86 1.86 0 0 1-1.2 2.6"/>
<path d="M262.9 166.6a2.16 2.16 0 0 1 2.7-1.5l1.4 .4a1.18 1.18 0 0 1 .7 1.1M263.1 166h.1M263.1 165.9l-.1 .5M263.2 166.5l.8-.7 1.1-.3 1.4 .2 1 .7-.6-.7-1.6-.3-1.4 .4-.8 .7M263.2 165.8l-.1 .7M263.4 171.4a2.94 2.94 0 0 1 4 .3 1.29 1.29 0 0 1-1.3 1.5 2.38 2.38 0 0 1-3-1.2zM263.8 171.1l-.4 .6a.34 .34 0 0 0-.2 .4 .34 .34 0 0 0 .4 .3l1.1 .8M264.6 165.5h1.6M264.7 170.9v2.3M265.7 170.8h-1.1M266.2 166.1h-1.6l1.1-.1 .9 .2M266.7 171.1l.3 .1a.36 .36 0 0 1 .3 .3 .36 .36 0 0 1-.1 .4l-.4 1"/>
<path d="M266.8 172.9l-1-.1-1.1 .4M266.8 171.1v1.8M267.5 166v.3M267.5 166h.1M281 174.3l5.7 3.3M281 169.4l4.3 2.5M285.3 173.5l1.9 1.6 1.5 .9M287.2 175.1v2.5h-6.2M288.7 176l.9 .8 .7 .9 .4 1.7M290.2 172.1l.4 1.6 .1 1.7M290.7 175.4v4.1l1.1 .9h5.3l3.4-2.8M290.8 171.8l1 3.2-1.1 .6 1.1 1v-1.6"/>
<path d="M297.1 175v1.6l1.1-1M298 171.8l-.9 3.2 1.1 .6 2.3-2.4M300.5 173.2v4.4h8.5M314.4 161.7v3.3M314.4 161.7a2.79 2.79 0 0 1 2.5-2.2 5.5 5.5 0 0 1 5.4 1.3l.3 .9v3.3M315.2 164a5.4 5.4 0 0 1 7 .4 1.87 1.87 0 0 1-1.5 2.6 5.4 5.4 0 0 1-5.8-1.1 1.45 1.45 0 0 1 .3-1.9zM315.8 166.8a1.84 1.84 0 0 1-1.4-1.7 1.84 1.84 0 0 1 1.2-1.8 5.7 5.7 0 0 1 6.8 .9 1.9 1.9 0 0 1-1.1 2.6M316.4 165.5l.9 .2 .7 .7M316.4 165.5l.4 .5 1.2 .4M317 164.3l-.6 1.2M317 164.3a2.92 2.92 0 0 1 3.6 .5 1.29 1.29 0 0 1-1.3 1.5l-1.3 .1M317 164.3a.95 .95 0 0 0-.6 1.2"/>
<path d="M318 164.1v2.3M318.9 163.9l-1.1 .1M319.9 164.2l.7 .7-.6 1.2M320 166.1l-.9-.1-1.1 .4M320 164.3v1.8M291.8 180.4v-3.8h5.3v3.8M302.5 195.7l.1-3.3a2.79 2.79 0 0 1 2.5-2.2 5.5 5.5 0 0 1 5.4 1.3l.3 .9v3.3M303.4 194.7a5.4 5.4 0 0 1 6.9 .5 1.87 1.87 0 0 1-1.5 2.6 5.4 5.4 0 0 1-5.8-1.2 1.45 1.45 0 0 1 .4-1.9zM303.7 190.7a6 6 0 0 1 5.9 0M303.9 197.5a1.83 1.83 0 0 1-1.3-1.7 1.83 1.83 0 0 1 1.2-1.8 5.7 5.7 0 0 1 6.8 .9 1.9 1.9 0 0 1-1.2 2.6M304.3 190.4a2.16 2.16 0 0 1 2.6-1.4l1.4 .4a1.18 1.18 0 0 1 .8 1M304.5 189.9h.1"/>
<path d="M304.5 189.8l-.1 .4M304.6 190.3l.8-.6 1.5-.3 1.4 .3 .6 .7-.5-.7-1.3-.4-1.7 .3-.9 .8M304.6 196.2l.4 .5 1.1 .4M304.6 196.2l.8 .3 .7 .6M304.6 189.7l-.2 .7M305.1 195l-.5 1.2M305.1 195a.95 .95 0 0 0-.5 1.2M305.1 195a2.92 2.92 0 0 1 3.7 .6 .95 .95 0 0 1-.6 1.2M306.1 194.8v2.3M307 194.7h-1.1M307.6 189.4h-1.6M307.6 190h-1.6l1.2-.1 .8 .2"/>
<path d="M308.1 195l.4 .3a.27 .27 0 0 1 .2 .2 .27 .27 0 0 1-.1 .3l-.4 1M308.2 196.8l-.8 .3h-1.3M308.2 196.8l-.9-.1-1.2 .4M308.2 195v1.8M308.9 189.9v.3"/>
<circle cx="121.7" cy="58.6" r=".08"/>
<circle cx="121.7" cy="58.7" r=".1"/>
<circle cx="122.2" cy="58.6" r=".1"/>
<circle cx="122.2" cy="58.6" r=".08"/>
<circle cx="126.7" cy="57.1" r=".08"/>
<circle cx="126.9" cy="57.8" r=".14"/>
<circle cx="137.2" cy="56.3" r=".07"/>
<circle cx="137.2" cy="56.3" r=".11"/>
<circle cx="137.7" cy="56.3" r=".08"/>
<circle cx="137.7" cy="56.3" r=".1"/>
<circle cx="141.4" cy="59.7" r=".1"/>
<circle cx="127.8" cy="63.3" r=".08"/>
<circle cx="127.8" cy="63.3" r=".1"/>
<circle cx="128.3" cy="63.3" r=".08"/>
<circle cx="128.3" cy="63.3" r=".1"/>
<circle cx="146.8" cy="64.1" r=".1"/>
<circle cx="146.8" cy="64.1" r=".08"/>
<circle cx="147.2" cy="64.1" r=".07"/>
<circle cx="147.2" cy="64.1" r=".1"/>
</g>
<g fill="#000">
<circle cx="119.6" cy="59.7" r=".25"/>
<circle cx="125.7" cy="59.7" r=".25"/>
<circle cx="119.3" cy="61.3" r=".25"/>
<circle cx="126" cy="63.5" r=".25"/>
<circle cx="126" cy="61.3" r=".25"/>
</g>
<g fill="#000" stroke="#000" stroke-width=".25">
<circle cx="117.6" cy="57.1" r=".24"/>
<circle cx="118.9" cy="56.4" r=".24"/>
<circle cx="120.3" cy="55.6" r=".24"/>
<circle cx="121.6" cy="54.9" r=".24"/>
<circle cx="121.6" cy="58.6" r=".24"/>
<circle cx="121.8" cy="58.6" r=".24"/>
<circle cx="122" cy="58.7" r=".24"/>
<circle cx="122" cy="58.6" r=".24"/>
<circle cx="122.1" cy="58.6" r=".24"/>
<circle cx="122.3" cy="58.6" r=".24"/>
<circle cx="122.3" cy="58.7" r=".24"/>
<circle cx="122.5" cy="58.7" r=".24"/>
<circle cx="122.9" cy="54.1" r=".24"/>
<circle cx="125.7" cy="55.5" r=".24"/>
<circle cx="126" cy="58.5" r=".24"/>
<circle cx="126.6" cy="57.5" r=".24"/>
<circle cx="126.6" cy="57.1" r=".24"/>
<circle cx="126.6" cy="57.8" r=".24"/>
<circle cx="126.6" cy="57.3" r=".24"/>
<circle cx="126.6" cy="56.9" r=".24"/>
<circle cx="126.6" cy="56.8" r=".24"/>
<circle cx="126.7" cy="57.3" r=".24"/>
<circle cx="126.7" cy="58" r=".24"/>
<circle cx="126.7" cy="58.1" r=".24"/>
<circle cx="126.7" cy="56.7" r=".24"/>
<circle cx="126.7" cy="57.4" r=".24"/>
<circle cx="126.7" cy="57.1" r=".24"/>
<circle cx="126.8" cy="57.5" r=".24"/>
<circle cx="126.8" cy="57.9" r=".24"/>
<circle cx="126.8" cy="56.7" r=".24"/>
<circle cx="126.8" cy="58" r=".24"/>
<circle cx="126.9" cy="57.1" r=".24"/>
<circle cx="126.9" cy="57.6" r=".24"/>
<circle cx="126.9" cy="56.7" r=".24"/>
<circle cx="127" cy="58" r=".24"/>
<circle cx="127" cy="57.2" r=".24"/>
<circle cx="127" cy="57.3" r=".24"/>
<circle cx="127" cy="57" r=".24"/>
<circle cx="127" cy="56.8" r=".24"/>
<circle cx="127" cy="57.1" r=".24"/>
<circle cx="127" cy="57.8" r=".24"/>
<circle cx="127" cy="57.5" r=".24"/>
<circle cx="127.5" cy="57.6" r=".24"/>
<circle cx="127.5" cy="57.3" r=".24"/>
<circle cx="127.5" cy="57.5" r=".24"/>
<circle cx="127.5" cy="57.2" r=".24"/>
<circle cx="127.5" cy="57.7" r=".24"/>
<circle cx="127.6" cy="57.7" r=".24"/>
<circle cx="127.7" cy="57.6" r=".24"/>
<circle cx="127.8" cy="57.6" r=".24"/>
<circle cx="127.8" cy="57.7" r=".24"/>
<circle cx="127.9" cy="57.3" r=".24"/>
<circle cx="127.9" cy="57.5" r=".24"/>
<circle cx="127.9" cy="57.4" r=".24"/>
<circle cx="127.9" cy="57.2" r=".24"/>
<circle cx="127.9" cy="57.6" r=".24"/>
<circle cx="128.4" cy="58.5" r=".24"/>
<circle cx="131.8" cy="59.8" r=".24"/>
<circle cx="131.8" cy="59.6" r=".24"/>
<circle cx="131.8" cy="60" r=".24"/>
<circle cx="137" cy="56.4" r=".24"/>
<circle cx="137.1" cy="56.3" r=".24"/>
<circle cx="137.2" cy="56.4" r=".24"/>
<circle cx="137.2" cy="56.2" r=".24"/>
<circle cx="137.4" cy="56.2" r=".24"/>
<circle cx="137.4" cy="56.4" r=".24"/>
<circle cx="137.7" cy="56.2" r=".24"/>
<circle cx="137.7" cy="56.4" r=".24"/>
<circle cx="139.3" cy="59.8" r=".24"/>
<circle cx="139.3" cy="60" r=".24"/>
<circle cx="139.3" cy="59.6" r=".24"/>
<circle cx="141.3" cy="59.6" r=".24"/>
<circle cx="141.3" cy="59.4" r=".24"/>
<circle cx="141.4" cy="59.6" r=".24"/>
<circle cx="141.5" cy="59.8" r=".24"/>
<circle cx="141.6" cy="59.4" r=".24"/>
<circle cx="141.6" cy="59.6" r=".24"/>
<circle cx="141.6" cy="59.8" r=".24"/>
<circle cx="143.7" cy="60" r=".24"/>
<circle cx="143.7" cy="57.4" r=".24"/>
<circle cx="143.7" cy="57.3" r=".24"/>
<circle cx="143.8" cy="57" r=".24"/>
<circle cx="143.9" cy="57.1" r=".24"/>
<circle cx="144" cy="57.4" r=".24"/>
<circle cx="144.1" cy="57.4" r=".24"/>
<circle cx="145.2" cy="58.2" r=".24"/>
<circle cx="146.7" cy="58.2" r=".24"/>
<circle cx="148.2" cy="60" r=".24"/>
<circle cx="148.2" cy="59.6" r=".24"/>
<circle cx="150.3" cy="59.8" r=".24"/>
<circle cx="150.3" cy="59.7" r=".24"/>
<circle cx="150.3" cy="60" r=".24"/>
<circle cx="150.4" cy="59.9" r=".24"/>
<circle cx="150.5" cy="59.9" r=".24"/>
<circle cx="150.5" cy="60" r=".24"/>
<circle cx="150.6" cy="59.7" r=".24"/>
<circle cx="150.6" cy="59.8" r=".24"/>
<circle cx="125.8" cy="60" r=".24"/>
<circle cx="126" cy="63.5" r=".24"/>
<circle cx="127.7" cy="63.3" r=".24"/>
<circle cx="127.8" cy="63.4" r=".24"/>
<circle cx="127.9" cy="63.3" r=".24"/>
<circle cx="128.1" cy="63.4" r=".24"/>
<circle cx="128.1" cy="63.2" r=".24"/>
<circle cx="128.2" cy="63.3" r=".24"/>
<circle cx="128.3" cy="63.4" r=".24"/>
<circle cx="128.4" cy="63.3" r=".24"/>
<circle cx="128.4" cy="63.4" r=".24"/>
<circle cx="128.6" cy="63.2" r=".24"/>
<circle cx="128.6" cy="63.4" r=".24"/>
<circle cx="131.8" cy="60.4" r=".24"/>
<circle cx="131.8" cy="61.7" r=".24"/>
<circle cx="131.8" cy="62.4" r=".24"/>
<circle cx="131.8" cy="61.3" r=".24"/>
<circle cx="131.8" cy="60.2" r=".24"/>
<circle cx="131.8" cy="61.5" r=".24"/>
<circle cx="131.8" cy="62" r=".24"/>
<circle cx="131.8" cy="62.6" r=".24"/>
<circle cx="131.8" cy="60.7" r=".24"/>
<circle cx="131.8" cy="62.8" r=".24"/>
<circle cx="131.8" cy="60.8" r=".24"/>
<circle cx="131.8" cy="62.2" r=".24"/>
<circle cx="131.8" cy="61.1" r=".24"/>
<circle cx="132.7" cy="63.4" r=".24"/>
<circle cx="133.2" cy="63.4" r=".24"/>
<circle cx="133.5" cy="63.4" r=".24"/>
<circle cx="133.9" cy="63.4" r=".24"/>
<circle cx="134.2" cy="63.4" r=".24"/>
<circle cx="134.7" cy="63.4" r=".24"/>
<circle cx="135" cy="63.4" r=".24"/>
<circle cx="136.2" cy="63.4" r=".24"/>
<circle cx="137.7" cy="63.4" r=".24"/>
<circle cx="138" cy="63.4" r=".24"/>
<circle cx="138.4" cy="63.4" r=".24"/>
<circle cx="139.3" cy="61.7" r=".24"/>
<circle cx="139.3" cy="61.5" r=".24"/>
<circle cx="139.3" cy="60.2" r=".24"/>
<circle cx="139.3" cy="60.8" r=".24"/>
<circle cx="139.3" cy="62.8" r=".24"/>
<circle cx="139.3" cy="62" r=".24"/>
<circle cx="139.3" cy="60.4" r=".24"/>
<circle cx="139.3" cy="62.4" r=".24"/>
<circle cx="139.3" cy="62.6" r=".24"/>
<circle cx="139.3" cy="61.3" r=".24"/>
<circle cx="139.3" cy="61.1" r=".24"/>
<circle cx="139.3" cy="62.2" r=".24"/>
<circle cx="139.3" cy="60.7" r=".24"/>
<circle cx="141.7" cy="63.7" r=".24"/>
<circle cx="141.9" cy="63.6" r=".24"/>
<circle cx="142" cy="63.6" r=".24"/>
<circle cx="142" cy="63.8" r=".24"/>
<circle cx="142.1" cy="63.8" r=".24"/>
<circle cx="142.1" cy="63.7" r=".24"/>
<circle cx="143.7" cy="60.7" r=".24"/>
<circle cx="143.7" cy="61.5" r=".24"/>
<circle cx="143.7" cy="61.8" r=".24"/>
<circle cx="143.7" cy="61.2" r=".24"/>
<circle cx="143.7" cy="60.4" r=".24"/>
<circle cx="143.7" cy="61.1" r=".24"/>
<circle cx="143.7" cy="60.2" r=".24"/>
<circle cx="143.7" cy="60.8" r=".24"/>
<circle cx="144.6" cy="62" r=".24"/>
<circle cx="145" cy="62" r=".24"/>
<circle cx="145.3" cy="62" r=".24"/>
<circle cx="145.8" cy="62" r=".24"/>
<circle cx="146.1" cy="62" r=".24"/>
<circle cx="146.5" cy="64.2" r=".24"/>
<circle cx="146.5" cy="62" r=".24"/>
<circle cx="146.6" cy="64.1" r=".24"/>
<circle cx="146.8" cy="64.2" r=".24"/>
<circle cx="146.8" cy="64" r=".24"/>
<circle cx="146.8" cy="62" r=".24"/>
<circle cx="146.9" cy="64.2" r=".24"/>
<circle cx="147.2" cy="64.2" r=".24"/>
<circle cx="147.2" cy="64" r=".24"/>
<circle cx="147.3" cy="62" r=".24"/>
<circle cx="147.3" cy="78.3" r=".24"/>
<circle cx="148.2" cy="62.7" r=".24"/>
<circle cx="148.2" cy="60.2" r=".24"/>
<circle cx="148.2" cy="61.5" r=".24"/>
<circle cx="148.2" cy="60.8" r=".24"/>
<circle cx="148.2" cy="60.4" r=".24"/>
<circle cx="148.2" cy="61.1" r=".24"/>
<circle cx="148.2" cy="61.8" r=".24"/>
<circle cx="148.2" cy="60.7" r=".24"/>
<circle cx="148.2" cy="61.2" r=".24"/>
<circle cx="149.8" cy="62.5" r=".24"/>
<circle cx="157.9" cy="85.1" r=".24"/>
<circle cx="296.2" cy="97.8" r=".24"/>
<circle cx="258.1" cy="113.1" r=".24"/>
<circle cx="259.3" cy="119.1" r=".24"/>
<circle cx="260.5" cy="117.2" r=".24"/>
<circle cx="262.7" cy="117.1" r=".24"/>
<circle cx="277" cy="108.9" r=".24"/>
<circle cx="245.9" cy="126.8" r=".24"/>
<circle cx="285.5" cy="132.4" r=".24"/>
<circle cx="291.1" cy="139.6" r=".24"/>
<circle cx="292.2" cy="139.6" r=".24"/>
<circle cx="293" cy="138.2" r=".24"/>
<circle cx="293.6" cy="138.2" r=".24"/>
<circle cx="293.9" cy="138.2" r=".24"/>
<circle cx="294.6" cy="138.2" r=".24"/>
<circle cx="294.9" cy="138.2" r=".24"/>
<circle cx="295.5" cy="138.2" r=".24"/>
<circle cx="295.9" cy="138.2" r=".24"/>
<circle cx="296.5" cy="138.2" r=".24"/>
<circle cx="296.9" cy="138.2" r=".24"/>
<circle cx="297.5" cy="138.2" r=".24"/>
<circle cx="298.2" cy="139.6" r=".24"/>
<circle cx="299.3" cy="139.6" r=".24"/>
<circle cx="304.7" cy="134" r=".24"/>
</g>
<!-- layer: Border -->
<g fill="none" stroke="#000" stroke-width=".25">
<path d="M15 .1h-15v15M20 10.1h390v276.9h-390zM65 5.1v5M115 5.1v5M165 5.1v5M215 5.1v10M265 5.1v5M315 5.1v5M365 5.1v5M405 .1h15v15M15 52.9h5M410 52.9h5"/>
<path d="M15 100.7h5M410 100.7h5M15 148.6h10M405 148.6h10M15 196.4h5M410 196.4h5M15 244.2h5M410 244.2h5M0 282.1v14.9h15M65 287v5M115 287v5M165 287v5"/>
<path d="M215 282.1v9.9M265 287v5M315 287v5M365 287v5M420 282.1v14.9h-15"/>
</g>
<!-- layer: TitleBlock -->
<path d="M230 240.1h180v46.9h-180zM230 250h180M254 240.1v9.9M288 240.1v46.9M349 240.1v46.9M288 260.1h122M349 277.1h61M359 277.1v9.9M395 277.1v9.9" fill="none" stroke="#000" stroke-width=".36"/>
<!-- layer: Annotations -->
<path d="M80.4 41.6l2.8 2.2-3.4-1.2zM215.9 56.1l.7 1-3.1 1.6zM119.9 96l3.2-1.5-2.5 2.5zM130.9 107.8l2.8-2.1-2 2.9zM150.1 113.2l-1.2 3.4-1-.6zM352.7 137l.9 .7-2.6 2.5zM265.7 174.2l-.7 3.5-1.1-.4zM313.4 168.4l3.3-1.3-2.7 2.3zM299.4 196.4l3.5 .1-3.3 1.1z" fill="#000" stroke="#000" stroke-width=".25"/>
<path d="M31.8 33.6h32.1l16.2 8.5M267.5 47.6h-39.2l-12 9M120.2 96.5l-36 25.8h-16.3M131.3 108.2l-25.3 26.3h-14.2M148.4 116.3l-16.2 29.9h-32.1M394 120.4h-28.2l-12.7 17M264.5 177.5l-9.3 25.3h-32.1M313.7 168.9l-58.5 33.9h-3.5h3.5l44.3-5.8" fill="none" stroke="#000" stroke-width=".25"/>
<use href="#words"/>
</svg>
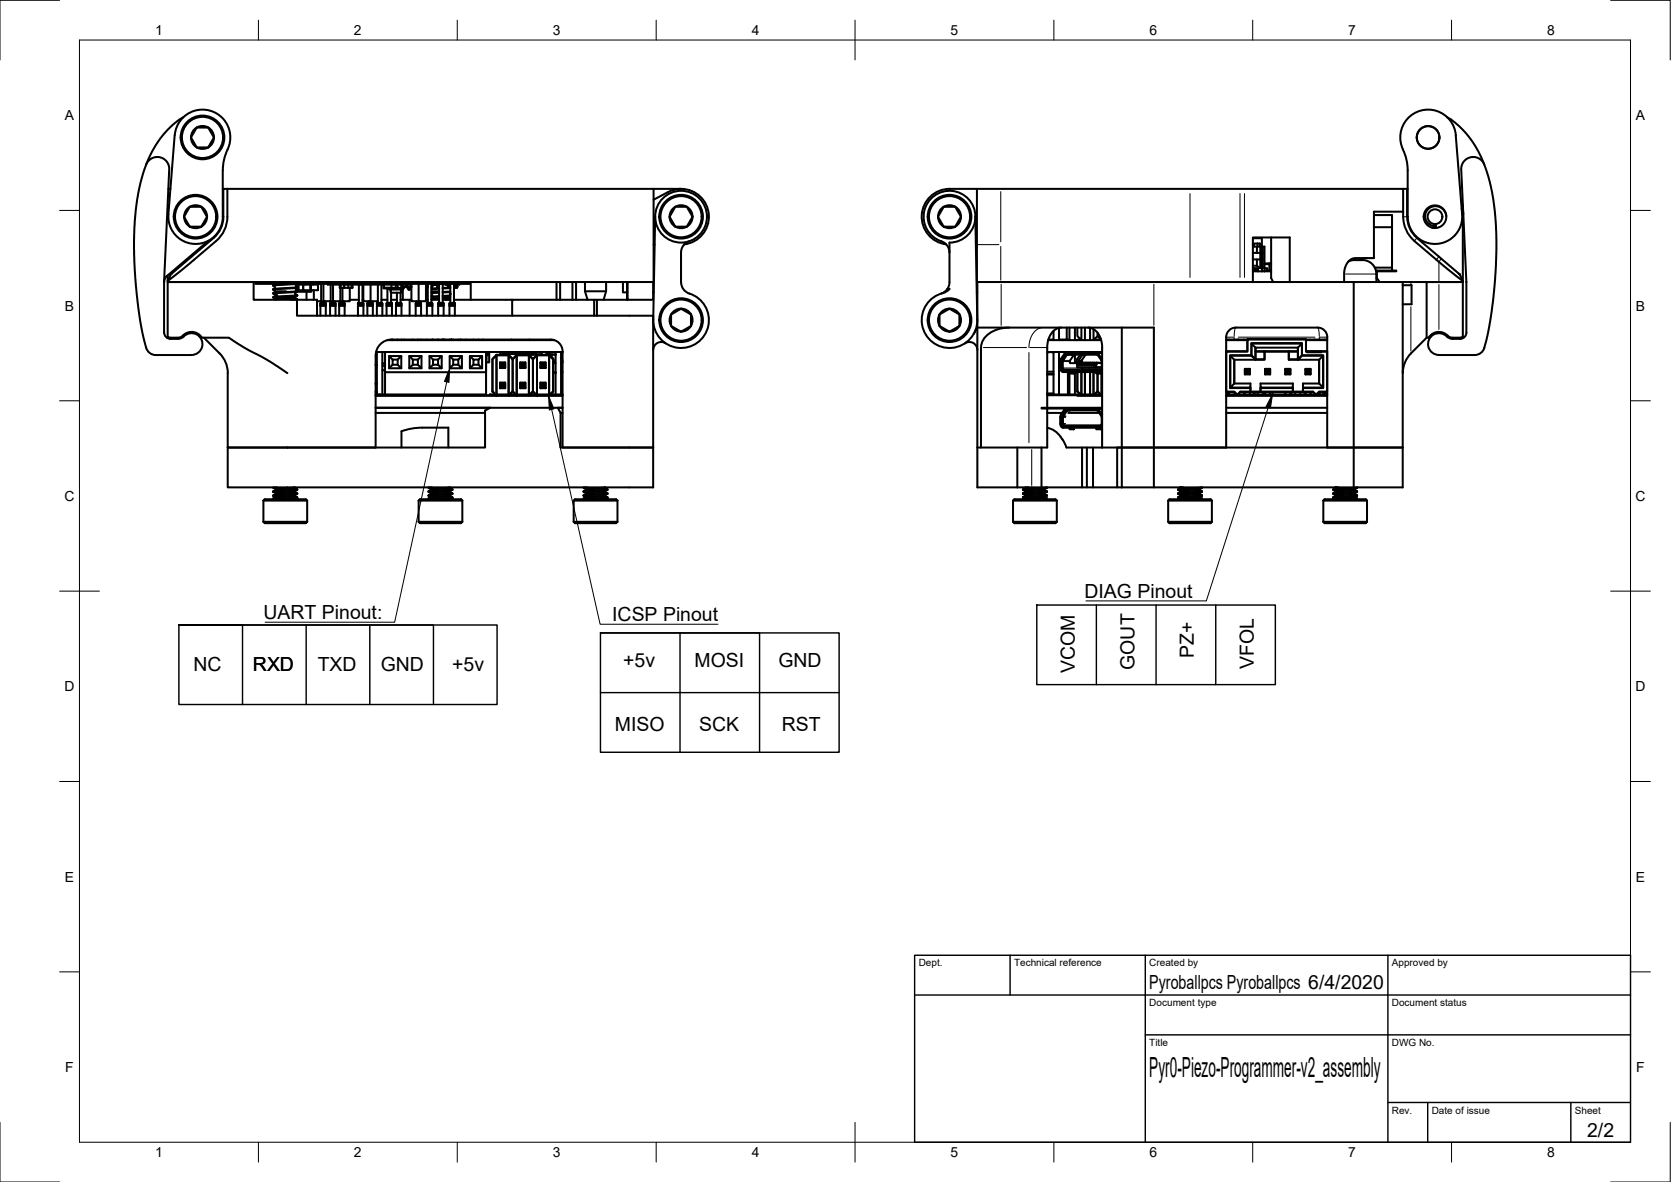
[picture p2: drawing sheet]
<svg xmlns="http://www.w3.org/2000/svg" width="420mm" height="297mm" viewBox="0 0 420 297" stroke-linecap="round" stroke-linejoin="round" font-family="sans-serif">
<defs><g id="words">
<text font-size="7" x="289" y="270.6">Pyr0-Piezo-Programmer-v2_assembly</text>
<g font-size="4.9">
<text x="66.3" y="155.7">UART Pinout:</text>
<text x="272.7" y="150.3">DIAG Pinout</text>
<text x="153.9" y="156.2">ICSP Pinout</text>
<text x="156.7" y="167.6">+5v</text>
<text x="174.6" y="167.6">MOSI</text>
<text x="195.7" y="167.6">GND</text>
<text x="300.2" y="165.4" transform="rotate(-90 300.2 165.4)">PZ+</text>
<text x="48.6" y="168.6">NC</text>
<text x="63.6" y="168.6">RXD</text>
<text x="79.9" y="168.6">TXD</text>
<text x="95.7" y="168.6">GND</text>
<text x="113.7" y="168.6">+5v</text>
<text x="270.3" y="169.1" transform="rotate(-90 270.3 169.1)">VCOM</text>
<text x="285.2" y="168.3" transform="rotate(-90 285.2 168.3)">GOUT</text>
<text x="315.2" y="168.1" transform="rotate(-90 315.2 168.1)">VFOL</text>
<text x="154.6" y="183.6">MISO</text>
<text x="175.8" y="183.6">SCK</text>
<text x="196.6" y="183.6">RST</text>
<text x="289" y="248.5">Pyroballpcs Pyroballpcs 6/4/2020</text>
<text x="399.1" y="285.7">2/2</text>
</g>
<g font-size="3.5">
<text x="39" y="8.8">1</text>
<text x="89" y="8.8">2</text>
<text x="139" y="8.8">3</text>
<text x="189" y="8.8">4</text>
<text x="239" y="8.8">5</text>
<text x="289" y="8.8">6</text>
<text x="339" y="8.8">7</text>
<text x="389" y="8.8">8</text>
<text x="16.3" y="30.2">A</text>
<text x="411.3" y="30.2">A</text>
<text x="16.3" y="78">B</text>
<text x="411.3" y="78">B</text>
<text x="16.2" y="125.9">C</text>
<text x="411.2" y="125.9">C</text>
<text x="16.2" y="173.7">D</text>
<text x="411.2" y="173.7">D</text>
<text x="16.3" y="221.6">E</text>
<text x="411.3" y="221.6">E</text>
<text x="16.4" y="269.4">F</text>
<text x="411.4" y="269.4">F</text>
<text x="39" y="290.8">1</text>
<text x="89" y="290.8">2</text>
<text x="139" y="290.8">3</text>
<text x="189" y="290.8">4</text>
<text x="239" y="290.8">5</text>
<text x="289" y="290.8">6</text>
<text x="339" y="290.8">7</text>
<text x="389" y="290.8">8</text>
</g>
<g font-size="2.5">
<text x="231" y="242.9">Dept.</text>
<text x="255" y="242.9">Technical reference</text>
<text x="289" y="242.9">Created by</text>
<text x="350" y="242.9">Approved by</text>
<text x="289" y="252.8">Document type</text>
<text x="350" y="252.8">Document status</text>
<text x="289" y="262.9">Title</text>
<text x="350" y="262.9">DWG No.</text>
<text x="350" y="279.9">Rev.</text>
<text x="360" y="279.9">Date of issue</text>
<text x="396" y="279.9">Sheet</text>
</g>
</g></defs>
<!-- layer: Visible -->
<g fill="none" stroke="#000" stroke-width=".51">
<path d="M46.1 29.5l-1.6 1-2.3 2.1-1.9 2.1-1.6 2.6-1.4 2.8-1 2.4-1 3.3-.6 3-.6 3.9-.3 4.3v8.9l1 11.5 .6 4.3 .9 4a3.8 3.8 0 0 0 1.8 3.3l1.1 .2h9a2.77 2.77 0 0 0 2.4-4 2.77 2.77 0 0 0-4.7-.4 4.1 4.1 0 0 1-3 .4 1.6 1.6 0 0 1-1.6-1.6M49.5 37h2.8M49.5 37l-1.3-2.1a.77 .77 0 0 1 .2-1l.9-1.5a.51 .51 0 0 1 .7-.3h2a.79 .79 0 0 1 .7 .7l.9 1.4a.78 .78 0 0 1-.2 1l-1.1 1.8M52.4 37a2.89 2.89 0 0 0 .7-4.3 2.89 2.89 0 0 0-4.4 0 2.89 2.89 0 0 0 .8 4.3M52.4 37l-1.5 .4-1.4-.4M363.9 29.5l2 1.3 2 1.9 1.9 2.3 1.5 2.3 1.4 2.7 1 2.8 .9 3 .8 3.7 .8 7.4v9.5l-.9 9.9-.8 5.8-.8 3.6a3.8 3.8 0 0 1-1.8 3.3l-1.1 .2h-9a2.78 2.78 0 0 1-2.4-4 2.78 2.78 0 0 1 4.7-.4 4 4 0 0 0 3 .4 1.6 1.6 0 0 0 1.6-1.6M36.7 41.4l.5-.8 .8-.7 .9-.4h1l1.1 .3 .6 .4 .6 .8 .3 .9-1.2 28.9M42.3 53.9l1.6-19.9a7 7 0 0 1 9.3-6.1 7 7 0 0 1 3.7 10.4l-.5 1.4-.3 2.3-.1 12.5M42.3 47.5h.5M42.4 53.9a6.8 6.8 0 0 0 6.5 7.4 6.8 6.8 0 0 0 7.1-6.8M47.7 57h2.9M47.7 57l-1.2-2.2a.94 .94 0 0 1 .2-1.1l.8-1.4a.59 .59 0 0 1 .8-.3h1.9a.92 .92 0 0 1 .9 .7l.8 1.4a.59 .59 0 0 1-.2 .9l-1.1 2"/>
<path d="M50.6 57a2.89 2.89 0 0 0 .8-4.4 2.89 2.89 0 0 0-4.4 0 2.89 2.89 0 0 0 .7 4.4M50.6 57l-1.4 .3-1.5-.3M56 47.5h.2M56.2 54.5v-7h1v7M56.2 54.5a7 7 0 0 1-2.5 5.3l-10.7 9.1-.8 1.7 4-3.2 8.1-6.8M57.2 47.5h114M57.2 54.5a8 8 0 0 1-2.8 6M164.3 47.5v23.4h-116.1M164.7 54.3l-.4 26a7 7 0 0 0 6.4 7.1 7 7 0 0 0 7.5-5.9 7 7 0 0 0-5.4-7.9 3 3 0 0 1-1.5-2.7v-7.9l.7-1.5 1.3-.9M169.8 57h2.9M169.8 57l-1.2-2.2a.67 .67 0 0 1 .1-.9l.9-1.6a.69 .69 0 0 1 .9-.3h1.8a.92 .92 0 0 1 .8 .7l.8 1.4a.93 .93 0 0 1-.2 1.2l-1 1.7M171.2 47.5a7 7 0 0 1 7 6.5 7 7 0 0 1-6.1 7.4"/>
<path d="M171.2 47.5l-1.1 .1-1.6 .4-4.2 2.2M172.7 57a2.89 2.89 0 0 0 .8-4.4 2.89 2.89 0 0 0-4.5 0 2.89 2.89 0 0 0 .8 4.4M172.7 57l-1.5 .3-1.4-.3M237.3 57h2.9M237.3 57l-1.2-2.2a.9 .9 0 0 1 .2-1.1l.8-1.4a.59 .59 0 0 1 .8-.3h1.9a.92 .92 0 0 1 .8 .7l.8 1.4a.67 .67 0 0 1-.1 1l-1.1 1.9M240.2 57a2.89 2.89 0 0 0 .8-4.4 2.89 2.89 0 0 0-4.5 0 2.89 2.89 0 0 0 .8 4.4M240.2 57l-1.5 .3-1.4-.3M245.2 54.3l.5 26a7 7 0 0 1-6.5 7.1 7 7 0 0 1-7.4-6.1 7 7 0 0 1 5.7-7.8l1.2-.9h-.5M245.6 47.5l.1 23.4M315 59.9h2.3v2.1M319.6 59.7v10.2l.5 1M345.5 54h4.5v14"/>
<path d="M345.5 57.1h4.5M352.8 53.2h-7.3v11.7h-4.8l-1.4 .5-.7 .9-.4 1.1-.2 1.1v2.4M352.8 47.5v7M352.8 54.5a8 8 0 0 0 2.8 6M353.8 47.5v7M353.8 54.5a7.1 7.1 0 0 0 2.5 5.3l10.8 9.1 .7 1.7-4.6-3.6-7.6-6.4M353.9 47.5h-115.2a7 7 0 0 0-6.9 6.6 7 7 0 0 0 6.1 7.3M354 54.5a6.8 6.8 0 0 0 7.1 6.8 6.8 6.8 0 0 0 6.5-7.4l-1.5-19.9a7 7 0 0 0-9.3-6.1 7 7 0 0 0-3.7 10.4l.5 1.4 .3 2.3v12.5M363.6 54.3l-.4-1.2-.8-.9-1.3-.4-1.2 .2-1.1 .8-.4 1.2 .1 1.3 .7 .9a2.46 2.46 0 0 0 1.9 .6l-1 .4M367.3 50.1l.4 1.6 .2 2.2M367.5 52.5l.3 2M367.8 54.5v16.4"/>
<path d="M373.2 41.4l-.5-.8-.7-.7-1.1-.4h-1l-.9 .3-.7 .5-.6 .7-.3 1.1 1.3 28.7M41.3 70.9v12.7M42 69.4l-.5 .6-.2 .9M42.2 69.2v1.7h6M48.2 70.9h15.6v4.4h10.9v4h89.5v33.2M48.2 70.9h-6v13.8l.5 .2 2.4-.1 2.2-1.3a3.1 3.1 0 0 1 3.5 1.4M52.4 60.5l-10.4 8.9M64.2 70.9v.4h7.4M69.1 73.2h2.8M69.1 73.2l.1 .2-.5 .2M69.1 71.3l-.4 .3M69.8 74.2l-1.1 .4"/>
<path d="M71.6 70.9v.4h.1M71.7 70.9v.4h46.5v-.4M73.1 71.3l-4 .3-.4 .2M74.1 74.7l-4.3 .3-.4 .3M74.1 74.7l-.3 .2-4.5 .4M74.1 74.8l.6 .3M74.3 73.6l-.1 .2 .5 .4-5.5 .4h-.4l-.1 .2M74.4 71.5v.5l.3 .1M74.5 72.4l.1 .5h.5M74.5 71.5v.5M74.6 71.3l-5.8 .4 .3 .3v.4l-.4 .3M74.7 71.3l-.3 .2"/>
<path d="M74.7 75.1l-1.6 .2M74.7 72.3l-.3 .2v.4l.3 .3-5.5 .4-.5 .2M74.7 72.1l-5.6 .5-.4 .2M74.7 75.3h5v4M74.7 74.3l-.6 .4M74.7 73.3l-.4 .3M74.7 75.3h-.1M74.7 74.3l-6 .5 .7 .4M74.7 73.3l-6 .5 .7 .5M74.7 72.3l-6 .5 .4 .2v.2M74.7 72.2v.1M74.7 73.2v.1"/>
<path d="M74.7 74.2v.1M74.7 75.1v.2M75 72.9v.4h3.3v-.4M75.1 72.9h2.9M75.1 71.3v1.6M76.2 71.3v1.6M76.2 72.9h.1M76.8 71.3v.2l-2.3-.1M76.8 71.5h1.3M77.1 73.3v2M78 71.5v1.4M78 72.9h.1"/>
<path d="M78.1 71.3v.2M78.1 71.3v1.6M78.2 71.5l.1 1.4M78.7 71.3v.2h-.6M78.7 71.5h1.3M78.9 72.9v2.4M80 71.3v1.6h-2M80.6 76.9h1.3M80.6 76.2v.4h1.3v-.4M80.6 76.2h1.3M80.6 76.9v2.4M80.6 76.6v.3"/>
<path d="M80.6 76.2h1.2M80.6 76.2h.1M80.8 71.3v4.4h-1.1M81.3 71.3v4.4h1.8v-4.2M81.3 75.7h-.5v.4M81.7 75.7v.4M81.8 76.2h.1M81.9 76.9v2.4M81.9 76.6v.3M82.4 71.3v.2h3l.1 .8M83 76.2v.4h1.4v-.4M83 76.2h1.4"/>
<path d="M83 76.6v.3M83.1 76.2h1.2M83.1 76.2h-.1M83.2 75.7v.4M83.7 71.5v4.2h-.6M84.1 75.7v.4M84.3 76.2h.1M84.4 76.9h-1.4v2.4M84.4 76.9v2.4M84.4 76.6v.3M85.3 76.9h1.4M85.3 76.2v.4h1.4v-.4"/>
<path d="M85.3 76.2h1.4M85.3 76.9v2.4M85.3 76.6v.3M85.4 76.2h1.2M85.4 76.2h-.1M85.4 71.3v.2h1.4v-.2M85.4 72.3h1.2M85.5 75.7v.4M85.6 72.3v3.4h-1.9M85.6 75.7h.5M85.7 71.3v1M86.1 72.3v3.4h1.8v-3.4"/>
<path d="M86.4 75.7v.4M86.5 71.3v1M86.6 72.3h.1M86.6 72.3h2M86.6 76.2h.1M86.7 76.9v2.4M86.7 76.6v.3M87.6 72.3h.1M87.6 71.3v.2h-.8M87.9 75.3h2.3M88.4 71.5v.8M88.6 72.3h.1"/>
<path d="M88.6 71.5v.8M90 76.9h1.4M90 76.2v.4h1.4v-.4M90 76.2h1.4M90 76.9v2.4M90 76.6v.3M90.1 76.2h1.2M90.1 76.2h-.1M90.2 71.5v4.6M90.5 71.3v.2h8.5v-.2M90.5 71.5h-2.9v.8M91.1 71.5v4.6"/>
<path d="M91.1 75.3h.3M91.3 76.2h.1M91.4 71.5v4.2h1.8v-4.2M91.4 76.9v2.4M91.4 76.6v.3M92.4 76.2v.4h1.3v-.4M92.4 76.2h1.3M92.4 76.6v.3M92.5 76.2h1.1M92.5 76.2h-.1M92.6 75.7v.4M93.5 75.7v.4"/>
<path d="M93.6 76.2h.1M93.7 76.6v.3M93.7 76.9h-1.3v2.4M93.7 76.9v2.4M94.8 76.9h1.3v2.4M94.8 76.2v.4h1.3v-.4M94.8 76.2h1.3M94.8 76.9v2.4M94.8 76.6v.3M94.8 76.2h.1M95 75.7v.4M95 71.5v4.2h-1.8"/>
<path d="M95.9 71.5v4.6M95.9 75.3h1.5M96.1 76.2h.1M96.2 76.6v.3M96.5 71.5v.9h.2l-.2-.1v-.8v.8h1.9M96.7 72.4h.2M96.9 72.4h1.7M96.9 72.4l1.5-.1v.2M97.2 76.9h1.4M97.2 76.2v.4h1.4v-.4M97.2 76.2h1.4M97.2 76.9v2.4"/>
<path d="M97.2 76.6v.3M97.3 76.2h1.2M97.3 76.2h-.1M97.3 72.4l.8 .1M97.4 72.4v.1M97.4 72.5v3.6M97.6 72.4l.4 .3M97.9 72.4v.1M98 72.4v.1M98.1 72.5h.3M98.1 72.4v.1M98.1 72.4l-.1 .4"/>
<path d="M98.1 72.8h2.9l-.1 .8h-2.6zM98.3 73.6v2.5M98.3 75.3h1.5M98.4 72.3h1.1M98.4 71.5v.8M98.4 72.5h.1M98.4 72.3h.1M98.5 76.2h.1M98.5 72.4l.3 .1M98.6 76.9v2.4M98.6 76.6v.3M98.6 72.3l.2 .2"/>
<path d="M98.8 72.4v.1M98.8 72.5h.1M98.9 72.4l.1 .1M99 72.4h.1M99.5 71.3v.2h-.5M99.5 72.3h.1M99.6 76.9h1.3M99.6 76.2v.4h1.3v-.4M99.6 76.2h1.3M99.6 76.9v2.4M99.6 76.6v.3M99.7 76.2h1.2"/>
<path d="M99.7 76.2h-.1M99.8 73.6v2.5M100 71.5v.9l-1.2-.1M100.7 73.6v2.5M100.7 75.3h.6M100.9 71.5l.1 .9h-1M100.9 76.2h.1M100.9 76.9v2.4M100.9 72.8l.4-.1v2.6M100.9 72.2h.3M101 76.6v.3M101 72.8h.1"/>
<path d="M101.1 72.4l-.1 .4M101.1 71.3v.2h-1.6v.8M101.1 72.8h.1M101.2 72.3h-.1M101.2 71.8v.5M101.3 75.3h2.1M101.6 72.1l-.1 .4-.4 .2M101.9 71.3v.2h-.8v.9M101.9 71.5h1.5M102.1 72.1h.2M102.1 72.1h.1M102.2 71.5v.6h-.8v-.6l-.2 .3"/>
<path d="M102.3 72.1h.1M102.3 72.1h.2M102.4 72.1h1M102.4 72.1v.1M102.5 72.1h.2M102.5 72.1h.1M102.5 72.1h.9M102.6 72.1h.1M102.7 72.1h.1M102.8 72.1h.1M102.9 72.2h.4l-.3 .6zM102.9 72.2h-.5l.3 .6h.2"/>
<path d="M102.9 72.1h-.2M102.9 72.1v.1M103 75.3v4M103.1 72.1h-.2M103.3 72.1v.1M103.4 72.1h.1M103.4 71.3v4.4h1.9M103.4 72h-1.2v-.5l.2 .6h-.2M104.5 76.9h1.4M104.5 76.2v.4h1.4v-.4M104.5 76.2h1.4M104.5 76.9v2.4"/>
<path d="M104.5 76.6v.3M104.6 76.2h1.2M104.6 76.2h-.1M104.7 75.7v.4M105.3 71.3v4.4h1.8v-4.4M105.7 75.7v.4M105.8 76.2h.1M105.9 76.9v2.4M105.9 76.6v.3M107.1 75.3h.5M107.3 71.3v.2h.3M107.3 76.9h1.4v2.4"/>
<path d="M107.3 76.2v.4h1.4v-.4M107.3 76.2h1.4M107.3 76.9v2.4M107.4 76.6v.3M107.4 76.2h1.2M107.4 76.2h-.1M107.5 72.1h.1M107.6 71.3v4.8M108.5 73.2h1.9M108.5 75.3h1.9M108.5 71.3v4.8M108.5 71.5h.4"/>
<path d="M108.6 76.2h.1M108.6 71.5v.6h-.1M108.7 76.6v.3M108.8 74.2h-.3M108.9 71.3v.2M109.9 72.3h.1M109.9 71.6l-1.3 .1M109.9 71.4l-1 .1M109.9 71.3l.1 1M109.9 71.5v.8M110 71.3v.2h.4M110 72.3h.4"/>
<path d="M110 72.3h.1M110.2 76.9h1.3M110.2 76.2v.4h1.3v-.4M110.2 76.2h1.3M110.2 76.9v2.4M110.2 76.6v.3M110.3 76.2h1.2M110.3 76.2h-.1M110.4 74.6l-1.9 .1M110.4 73.5l-1.9 .2M110.4 72.5l-1.9 .2M110.4 74.4l-1.9 .1"/>
<path d="M110.4 73.4l-1.9 .1M110.4 72.4l-1.9 .1M110.4 74.9l-1.9 .2M110.4 75.1l-1.9 .1M110.4 71.3v4.8M111.3 71.4l.8-.1 .1 .2M111.3 71.3v4.8M111.3 75.3h1.9M111.5 76.2h.1M111.5 76.9v2.4M111.6 76.6v.3M112.1 71.5h-.8"/>
<path d="M112.2 71.5h1M112.2 71.3v.2M112.6 71.5l.1 .6M112.7 71.5v.6M112.7 72.1h.2M112.8 71.5l.1 .5M112.8 72.3l-1.5 .1M112.8 72.1v.2M112.9 72.3h.1M112.9 72.3l.3 .1-1.9 .1M112.9 71.3v1M113 76.9h1.4v2.4"/>
<path d="M113 76.2v.4h1.4v-.4M113 76.2h1.4M113 76.9v2.4M113 76.6v.3M113.1 76.2h1.2M113.1 74.7l-1.8 .2M113.1 74.7l-.2 .2-1.6 .1M113.1 76.2h-.1M113.1 74.8l.1 .1M113.2 74.4l-1.9 .1M113.2 73.4l-1.9 .1M113.2 75.3h-1.1"/>
<path d="M113.2 74.3l-1.9 .1M113.2 73.2l-1.9 .2M113.2 71.3v4.8M113.2 74.6l-.1 .1M113.2 73.8h.1M114.2 75.3h14.6M114.2 71.3v4.8M114.2 72.3v.2M114.3 76.2h.1M114.4 76.6v.3M114.5 71.3v1h-.3M114.5 72.3h.4"/>
<path d="M114.5 72.3h.1M114.9 71.3v1M114.9 72.3h.1M115 71.5l-.1 .6M115.5 71.3v.2h-1.3M118.4 70.9v4.4M128.8 79.3v-4h20.6v4M139.9 70.9v4.4M140.8 70.9v4.4M143.9 70.9v4.4M144.8 70.9v4.4M147.1 73.2h5.3"/>
<path d="M147.1 73.2l.6 2.1M147.1 70.9v2.3M150.1 75.3v4M152.4 70.9v2.3l-.6 2.1M156.6 70.9v2.6h1.1M164.2 70.9v4.4h-6.5v-4.4v4.4h-8.3M164.2 73.5h.2M164.3 61.5h.3M173.7 79v2.9M173.7 79l-2.1-1.2a.56 .56 0 0 0-.9 .1l-1.6 .9a.69 .69 0 0 0-.4 .9v1.8a.71 .71 0 0 0 .7 .8l1.5 .8a.92 .92 0 0 0 1.1-.2l1.7-1M173.8 79l.3 1.5-.3 1.4M173.8 79a2.89 2.89 0 0 0-4.4-.8 2.89 2.89 0 0 0 0 4.5 2.89 2.89 0 0 0 4.4-.8"/>
<path d="M236.2 79v2.9M236.2 79l2.2-1.2a.56 .56 0 0 1 .9 .1l1.6 .9a.69 .69 0 0 1 .3 .9v1.8a.71 .71 0 0 1-.6 .8l-1.5 .8a.92 .92 0 0 1-1.1-.2l-1.8-1M236.2 79a2.89 2.89 0 0 1 4.4-.8 2.89 2.89 0 0 1 0 4.5 2.89 2.89 0 0 1-4.4-.8M236.2 79l-.3 1.5 .3 1.4M236.7 60.6l.9 .5 .6 .7 .4 .9 .1 .8M236.7 60.6a6.5 6.5 0 0 1-2.8-10.5 6.5 6.5 0 0 1 10.8 1.7 6.5 6.5 0 0 1-6 9.2v9.9l-.2 1.1-.3 .6M238.2 72.6l-.8 .8-.8 .4M245.4 61.5h.2M245.6 73.5h.1M245.7 70.9h116.1M245.7 70.9v51.6h26.4M315 61.2h1.2"/>
<path d="M315 67.6h1.3v.6h-1.3M315 65.2h1.9M315 61.8l.3-.4v.6h2M315 70.9v-11.2h9.3v11.2M315 68h1.2M315 66.8h1M315 61.2v.2h.3M315 61.4h.1M316 62v1.5h-1M316 63.5h.9v1.7M316 65.2v1.6M316 66.8l.9 .6"/>
<path d="M316.2 61.2v.8M316.2 61.2h.6v.8M316.3 68.2h3.3M316.9 65.2v2.2h-1.9M316.9 62v1.5M317.3 62h.6v6.2M317.3 63.5h.2v1.7M317.3 62v6.2M317.3 65.2h.2M317.3 67.3l.2 .1M317.5 65.2v2.2h-.2M317.5 62v1.5"/>
<path d="M317.9 67.4h.7v.6M317.9 68h1.7M317.9 66.2h1.7M319.2 66.2v.2h-1.3M319.2 68l.1-.3 .1 .3M319.6 66.4h-.4v1.6M339.1 65.7l1.1-.3h1.6a3.7 3.7 0 0 1 4.3 3.5v2M340.4 70.9v51.6M343.7 64.9l-1.9 .5M345.7 67.3h4.3M345.9 68h5.2v.2h-5.1M346.1 69.9h.1"/>
<path d="M346.2 68.2v1.7l.7 1M352.7 71.7h2.2v4.8h-2.2M352.7 70.9v51.6h-70.6M361.8 70.9h6M361.8 70.9h-3.1v14M367.8 70.9v13.8l-.5 .2-2.4-.1-2.3-1.3a3.1 3.1 0 0 0-3.4 1.4h-.5M368.7 70.9v12.7M368.7 70.8v.1M50.8 84.9h6.8l3.9 2.5 6.3 3.4 4.5 3M51.3 84.9l3.9 3.9a7 7 0 0 1 2.1 5v18.7h15M94.4 99.5h30.4M94.4 99.3h28.8"/>
<path d="M94.4 99.1h1M94.4 89.3v23.2h-22.1M94.4 98.5h.4M94.4 96.5h.4M94.4 91.8h.4M94.4 98.4h.4M94.4 96.4h.4M94.4 91.6h.4M94.5 89.3a4 4 0 0 1 4-4h40a2.99 2.99 0 0 1 3 3v24.2h22.7M94.6 88.5h2.2M94.8 88.5v10.6M95.6 99.1h-.2v.2"/>
<path d="M96.1 88.5v10.6M96.1 91.3h.7M96.1 93h.7M96.8 99.3v-.2h25.4v.2M96.8 88.5h25.4v5h-25.4zM96.8 93.5v5.6h-1.2v.2M96.8 91.5l-.2 .4h-.5M97.4 85.5h42M97.8 89.5v3l.9-.8M98.6 85.3v.2M98.7 90.4l-.9-.9h3.1l-.9 .9M98.7 91.7h1.3l.9 .8h-3.1"/>
<path d="M98.7 85.3v.2M100 90.4h-1.3v1.3M100 85.3v.2M100 90.4v1.3M100.9 89.5v3M100.9 85.3v.2M101.7 85.3v.2M102.9 89.5v3l.9-.8M103.8 90.4l-.9-.9h3.1l-.9 .9M103.8 91.7h1.3l.9 .8h-3.1M103.8 85.3v.2M105.1 90.4h-1.3v1.3"/>
<path d="M105.1 85.3v.2M105.1 90.4v1.3M105.9 85.3v.2M106 89.5v3M107.3 85.3v.2M108 89.5v3l.9-.8M108.7 85.3v.2M108.9 90.4l-.9-.9h3.1l-.9 .9M108.9 91.7h1.3l.9 .8h-3.1M108.9 85.3v.2M110.2 90.4h-1.3v1.3M110.2 85.3v.2"/>
<path d="M110.2 90.4v1.3M111.1 89.5v3M111.3 85.3v.2M111.4 85.3v.1M111.4 85.4l.1 .1M111.8 85.3v.2M111.8 85.4v.1M113 85.4l.1 .1M113 85.3v.2M113.1 89.5v3l.9-.8M113.5 85.3h.1M113.4 85.3v.2"/>
<path d="M113.6 85.3v.2M114 90.4l-.9-.9h3l-.9 .9M114 91.7h1.2l.9 .8h-3M114 85.3v.2M115.2 90.4h-1.2v1.3M115.2 85.3v.2M115.2 90.4v1.3M115.8 85.3v.2l.1-.2M116.1 89.5v3M117.2 85.3v.2M118.2 89.5v3l.8-.8M119 90.4l-.8-.9h3l-.9 .9"/>
<path d="M119 91.7h1.3l.9 .8h-3M119 85.3v.2M120.3 90.4h-1.3v1.3M120.3 85.3v.2M120.3 90.4v1.3M121.2 89.5v3M121.4 85.3v.2M122.2 91.1h.7M122.2 88.6h.5v.6l-.5 .1M122.2 88.5h19.3M122.2 88.5v10.6M122.3 88.5l.4 .1v.6l-.2 .1"/>
<path d="M122.8 88.5v.8h-.5v1.8M122.9 88.5h.1M123 88.5l-.1 2.5M123.2 99.1h15.9v.2h-15.9zM124.7 99.3l.1 .2M124.8 89.3v9.8v-9.9l-1 1v8.1l.9 .8M124.8 89.2h3.1M124.8 89.3h3.1M124.8 89.3l-1 1v8.2l.7 .6M124.8 99.3v.2M125.7 91.1l.5 .4h.4l.4-.4M125.7 96.1l.5 .5h.4l.4-.5"/>
<path d="M126.2 91.5v.6M126.2 96.6v.6M126.3 88.5l-.4 .2-.2 .5M126.4 89l-.1 .2M126.4 89h.7M126.4 89.1l-.3 .1M126.4 88.8v.2M126.6 91.6l.4-.4v1.3h-1.3v-1.3l.5 .4h.4v.5l.4 .4M126.6 92.1h-.4l-.5 .4M126.6 96.7l.4-.4v1.3h-1.3v-1.3l.5 .4h.4v.5l.4 .4M126.6 97.2h-.4l-.5 .4M126.6 91.5v.4l.4 .5v-1.3h-1.3v1.3l.5-.5h.4"/>
<path d="M126.6 96.6v.4l.4 .4v-1.3h-1.3v1.3l.5-.4h.4M127.1 88.5v.5h2.4v-.5M127.1 88.7l-.6 .1M127.9 99.3v.2h-3.1M128 99.3l-.1 .2h2M128.3 99.1h.1M128.6 85.3l-.1 .2M128.9 90.2l-1-1v9.9v-9.8l1 1M128.9 98.5l.7 .6M128.9 90.3v8.2M128.9 98.5l-.7 .6M128.9 98.3l.8 .8"/>
<path d="M128.9 98.3l-.8 .8M129.5 88.7l.7 .1M129.5 89h.7M129.8 99.3l.1 .2M129.9 88.5v.2M129.9 89.3v9.8v-9.9l-1 1v8.1M129.9 89.2h8.2M129.9 89.3l-1 1M129.9 99.3v.2M129.9 89.3h3.1M130.2 88.8v.4M130.2 88.8h.1"/>
<path d="M130.3 88.5v.3h.5M130.4 88.8v.2M130.4 89v.1M130.6 88.8l.1 .3M130.8 91.1l.4 .4h.5l.4-.4M130.8 96.1l.4 .5h.5l.4-.5M130.8 88.5v.3M130.8 88.8h.4M131 88.8l.1 .3M131.2 88.5v.3h.5M131.2 91.5v.6M131.2 96.6v.6"/>
<path d="M131.3 88.8v.3M131.5 88.8l.2 .2M131.7 89v.1M131.7 91.6l.4-.4v1.3h-1.3v-1.3l.4 .4h.5v.5l.4 .4M131.7 92.1h-.5l-.4 .4M131.7 96.7l.4-.4v1.3h-1.3v-1.3l.4 .4h.5v.5l.4 .4M131.7 97.2h-.5l-.4 .4M131.7 91.5v.4l.4 .5v-1.3h-1.3v1.3l.4-.5h.5M131.7 96.6v.4l.4 .4v-1.3h-1.3v1.3l.4-.4h.5M131.7 88.5v.3M131.7 88.8h.4M131.9 88.8l.1 .3"/>
<path d="M132.1 88.5v.3h.6M132.2 88.8v.3M132.5 88.8l.1 .3M132.7 88.5v.3M132.7 88.8h.3M132.8 88.8l.1 .3M133 99.3v.2h-3.1M133 88.5v.3h.8l.1 .3M133.1 99.3l-.1 .2h2M133.1 88.8l.1 .3M133.2 85.3l-.1 .2M133.4 88.8l.1 .3"/>
<path d="M133.7 88.5l.3 .2 .1 .4M133.9 88.5h.8M134 98.5v-8.2l-1-1v9.8v-9.9l1 1v8.1l-.8 .8M134 88.7h.7M134 98.5l-.7 .6M134 98.5l.7 .6M134 98.3l.8 .8M134.7 88.5v.6h1M134.9 99.3l.1 .2M135 89.3l-1 1M135 99.3v.2M135.2 89.1h.1"/>
<path d="M135.6 89.1l.3 .1M135.7 88.5l.4 .2 .2 .5M135.9 91.1l.4 .4h.5l.4-.4M135.9 96.1l.4 .5h.5l.4-.5M136.3 91.5v.6M136.3 96.6v.6M136.8 91.6l.4-.4v1.3h-1.3v-1.3l.4 .4h.5v.5l.4 .4M136.8 92.1h-.5l-.4 .4M136.8 96.7l.4-.4v1.3h-1.3v-1.3l.4 .4h.5v.5l.4 .4M136.8 97.2h-.5l-.4 .4M136.8 91.5v.4l.4 .5v-1.3h-1.3v1.3l.4-.5h.5M136.8 96.6v.4l.4 .4v-1.3h-1.3v1.3l.4-.4h.5"/>
<path d="M137 88.5l.4 .2 .2 .5M137.2 88.5h1.1M137.5 89l.1 .1M137.6 89.1l.1 .1M137.7 88.5l.3 .1 1.1 1.5 .3 1.1M137.9 88.5v.1M138.1 99.3v.2h-3.1M138.1 89.3h-3.1v9.8v-9.9l-1 1M138.2 99.3l-.1 .2h3.4M138.3 99.1l.8-.8v-8.1l-1-1v9.9v-9.8l1 1v8.2l-.7 .6M138.4 88.5h.1M138.7 88.5h-.3"/>
<path d="M138.8 88.5h-.1M139.1 93.5h.6l-.1 .2 .1 .1M139.1 99.3h2.4M139.1 99.1h2.4M139.4 91.3h.3M139.6 93.7h.1M139.7 89.1h-.1M139.7 89.1h-1.3h1.3M139.7 88.5v10.6M139.7 89.1h.1M141.1 90l.3 .8M141.1 88.5v10.6"/>
<path d="M141.1 93.5h.4M141.1 88.5h.4M141.1 91.3h.2M141.2 93.5l-.1 .3M141.4 90.9v.1M141.4 91l-.1 .2M167.4 86.3a2 2 0 0 0-3.1 1.6M242.6 86.3a2 2 0 0 1 3.1 1.6M244.8 84l.9-1.7h44.4v40.2M253.8 82.3a7.3 7.3 0 0 0-6.8 3.4l-.3 1.6v25.2M263.3 98.9h1.6M263.3 93.4h1.6"/>
<path d="M263.3 94h1.6M263.3 88.5h13.7M263.3 99h1.6M263.3 94.1h1.6M263.3 99.1h8.3v.2M263.3 88.6l.8-.1 .8 .1M263.3 99.3h13.8M263.6 85.5h13.3M263.6 85.3h1.3M264.7 88.5l.2 .1M264.9 83.1v2.4M264.9 88.5v10.6"/>
<path d="M266.3 82.4v3.1M266.3 88.5v10.6M266.9 82.3a4.2 4.2 0 0 0-3.5 4.1l-.1 16.1M266.9 90.3l-.2 2.2 .2 .5 .4 .3h9.2a.71 .71 0 0 0 .6-.8M267.3 90.6l-.1 1.9 .3 .4M267.3 90.6l1-1.5 7.7 .1a3.1 3.1 0 0 1 1 3.5l-.3 .2M267.5 92.9h9.2M268.2 88.7h7.4M268.2 88.7l-.4 .3-.9 1.3M268.2 85.3h.7M268.2 82.3v3h-1.9M268.5 88.5h.1"/>
<path d="M268.5 93.5v5.6M268.8 93.5l.1 .4h1.1M268.9 82.3v3.2M268.9 88.5h.1M268.9 93.8v5.3M269 88.5h.1M269.1 90.6v.6M269.1 91.3h1.9M269.8 93.5l.2 .4 .4-.2-.1-.2M269.9 88.5h.1M270 88.5h.3M270.2 89.1l-1.1 1.5"/>
<path d="M270.3 82.3v3.2M270.3 89.1v2.2M270.3 93.8v5.3M270.4 88.5h.1M270.9 91.6v.8h6.1M270.9 91.7h4.3l.1 .4 .2 .2M270.9 91.6h4.5M270.9 82.3v2.2l1 1v-3.2M270.9 99.5h6.2M270.9 93.5v5l.7 .6M270.9 98.3l.8 .8M270.9 90.1l-.3 1.1"/>
<path d="M271 91.4l-.1 .2M271 91.3l.4-.1-.4 .4M271.2 88.5h.1M271.3 88.5h.3M271.4 91.5l-.1 .1M271.6 99.1h5.5M271.6 89.1l-.7 1.1M271.6 88.5h.1M271.8 85.3l-1.2 .2M271.9 90.7v.3M271.9 93.5v5.6M271.9 91.3l-.5 .2"/>
<path d="M272 91.2h.3l-.4 .4M272 91.2h-.6v.3M272 91.2l-.2 .4M272 90.5v.7M272 92.4l.4 .4h4.5M272.3 91.5l-.1 .1M272.3 89.1l-1.1 1.5-.2 .6M272.3 91.5h.1M272.6 91.3h.2M272.6 91.3l-.3 .2M272.8 82.3v3.2M272.8 93.5v5.6"/>
<path d="M272.9 91.2h.4l-.5 .4M272.9 91.2h-.6v.3M272.9 91.2l-.1 .4M273 88.5h-.2M273.1 89.1l-1.1 1.5v.5M273.2 91.5l-.1 .1M273.3 91.5h-.1M273.6 82.3a4.2 4.2 0 0 1 3.5 4.1v.9M273.7 91.3l-.4 .2M273.8 92.8l.1 .1M273.8 91.2h.4l-.5 .4M273.8 91.2h-.5v.3"/>
<path d="M273.8 91.2l-.1 .4M273.9 88.5h.1M274.1 82.4v3.1M274.1 93.5v5.6M274.2 91.5l-.2 .1M274.7 91.3l-.5 .2M274.7 91.2h.4l-.4 .4M274.7 91.2h-.5v.3M274.7 91.2l-.1 .4M275 82.7v2.8l1-1M275 93.5v5.6M275.1 91.5l-.2 .1"/>
<path d="M275.1 85.3h1.7M275.1 91.5h.1M275.2 99.1l.8-.8 .8 .8M275.2 91.7l.5-.1-.2 .7M275.2 88.5h.1M275.4 91.3h.2M275.4 91.3l-.3 .2M275.5 93.5l.2 .4h1M275.5 92.3v.1M275.6 88.5l.5 .3 1 1.5M275.6 88.7l.4 .3 .9 1.3M275.7 91.2h-.6v.3"/>
<path d="M275.8 91.2l-.3 .4M275.8 91.2h1.2M275.8 91.2l-.1 .4M276 83.7v.8l.8 .8M276 98.5l.6 .6M276 93.9v4.6M276 98.5l-.7 .6M276.3 88.5h-.2M276.6 88.5h-.1M276.9 90.3l.2 .5M277 93.8v5.3M277.1 93.5v.1"/>
<path d="M277.1 88.5h-9.1l-1.4 2.1a4.5 4.5 0 0 0 .2 2.6l.5 .3h9.8M277.1 87.3v25.2M277.1 93l-.6 .5 .2 .4 .4-.2M282.1 82.3v40.2M308.3 98.5v14h-31.2M308.3 88.3v-3.6a2.4 2.4 0 0 1 2.4-2.4h20.6a2.4 2.4 0 0 1 2.4 2.4v3.6M308.3 85.3h5.3M308.3 99.5h25.4M308.3 85.5h5.3M308.3 99.3h.3M308.3 99.1h.3M308.6 99.1h24.8v.2h-24.8z"/>
<path d="M309 85.3v.2M309 98.5v.6M309.3 97.4v-8.1h5.4v-3.1h12.7v3.1h5.3v8.1h-5.1v1M309.3 89.4l1 1M310.3 96.4h4.1v1h-5.1zM310.3 90.4v6M310.4 85.3v.2M310.4 98.6v.5M310.9 99.1l-.6-.6h-2v-10.1h5.3v-3.1h14.8v3.1h.2v.1l5.1-.1v10.1h-2l-.6 .6M311.1 99.1l.8-.7h18.3l.7 .7M311.3 85.3v.2M311.4 85.3v.2"/>
<path d="M311.4 99v.1M312.8 85.3v.2M312.8 98.5v.6M313 98.5v.6M313 92.7l.4 .3M313.4 93.2l-.4-.4v1.3h1.3v-1.3l-.4 .4M313.4 93.2h.5v.5h-.5zM313.4 93.6l-.4 .4v-1.3h1.3v1.3l-.4-.4M313.4 93h.5v.6h-.5zM313.4 93.7l-.4 .4M313.9 93.7l.4 .4M314.3 98.5v.6"/>
<path d="M314.3 92.7l-.4 .3M314.4 97.5h-5.1v-8.1h5.4v-3.1h12.7v3.1h5.3v8.1h-5.1v1M314.4 97.4v1.1M314.7 86.3l1 1.1v2.9M314.7 89.3l1 1M315.2 98.5v.6M315.5 98.5v.6M315.7 88.4h2.3v2h-7.7M315.7 88.3h2.3v2h-2.3M316.2 98.5v.6M316.9 98.5h-5l-.6 .6M316.9 98.5h13.3l.6 .6"/>
<path d="M316.9 96.4h8.2v1h-8.2zM316.9 97.5h8.2M316.9 97.4v1.1M317.6 98.5v.6M318 88.4h8.3M318 88.3h8.3M318.1 98.5v.6M318.1 92.7l.4 .3M318.5 93.2l-.4-.4v1.3h1.3v-1.3l-.4 .4M318.5 93.2h.5v.5h-.5zM318.5 93.6l-.4 .4v-1.3h1.3v1.3l-.4-.4M318.5 93h.5v.6h-.5z"/>
<path d="M318.5 93.7l-.4 .4M319 93.7l.4 .4M319.4 98.5v.6M319.4 92.7l-.4 .3M320 98.5v.6M323.2 98.5v.6M323.2 92.7l.3 .3M323.5 93.2l-.3-.4v1.3h1.2v-1.3l-.3 .4M323.5 93.2h.6v.5h-.6zM323.5 93.6l-.3 .4v-1.3h1.2v1.3l-.3-.4M323.5 93h.6v.6h-.6zM323.5 93.7l-.3 .4"/>
<path d="M324.1 88.3v2.1h2.2v-3h-10.6v3l-1-1M324.1 90.3h2.2M324.1 93.7l.3 .4M324.4 98.5v.6M324.4 92.7l-.3 .3M324.7 98.5v.6M325.1 97.4v1.1M325.6 98.5v.6M327 98.5v.6M327.4 89.4l-1.1 1h5.4l1-1M327.4 86.3l-1.1 1.1v2.9M327.4 89.3l-1.1 1"/>
<path d="M327.6 97.4v-1h4.1v-6v6l1 1M328 98.5v.6M328.3 92.7l.3 .3v.6h.6v-.6h-.6M328.3 98.5v.6M328.4 85.3h5.3M328.4 85.5h5.3M328.6 93.2h.6v.5h-.6v-.5l-.3-.4v1.3h1.2v-1.3l-.3 .4M328.6 93.6l-.3 .4v-1.3h1.2v1.3l-.3-.4M328.6 93.7l-.3 .4M328.6 88.4h3.6M328.6 88.3h3.6M329.2 93.7l.3 .4"/>
<path d="M329.4 85.3v.2M329.5 98.5v.6M329.5 92.7l-.3 .3M330.4 88.3v.1M330.5 85.3v.2M330.5 98.9v.2M331.9 85.3v.2M331.9 98.5v.6M332.2 88.4h-3.6v-.1h-.2v-3.1h-14.8v3.1h-5.3v10.1h2l.8 .7M332.2 88.4v-.1h1.5v10.1h-2l-.7 .7M333.1 85.3l.1 .2M333.4 99.1h.2v.2"/>
<path d="M333.4 99.3h.3M333.6 99.1h.1M333.7 98.9h-1v-.4v.5M333.7 99h-1l.1 .1M333.7 98.5v14h19h-71.8v10h1.2M358.7 84.9l-3.9 3.9a7 7 0 0 0-2.1 5M72.3 112.5h-15v10h106.9v-10M94.4 102.5h28.9M94.4 103.8h27.6M106.2 107.5h6.5v5M106.2 107.5l-3.1 .3-2.1 .6-.1 4.1M123.3 102.5h17l.6 1.3v8.7h23.3"/>
<path d="M123.3 102.5l-1.3 .7v9.3h-49.7M140.3 102.5h1.2M140.9 103.8h.6M255.8 112.5v10M261.9 112.5v10M261.9 102.5h14.5M263.3 102.7v9.8h-17.6M263.3 103.8h3.8M263.3 107.5a5.6 5.6 0 0 1 3.8 2.9M267.1 110.4l1 2.1h9M267.3 104.6l-.1 1.9 .3 .4M267.3 104.6l1.1-1.5h7.4l1.1 1.5"/>
<path d="M267.5 106.9h9.2M267.9 102.7l-1.3 1.9a4.5 4.5 0 0 0 .2 2.6l.5 .3h9.8h-.6M268.6 103.8h7.8M268.8 107.5l.1 .4h1.1M269.8 107.5l.2 .4M272.1 112.5v10h1.2M273.3 112.5v10h1.5M274.8 112.5v10h6.1M275.5 107.5l.2 .4h1M276 102.7l1.1 1.6M276.4 102.7h.7M276.5 107.5l.3 .4"/>
<path d="M276.9 104.3l-1.1-1.5-7.6-.1-.4 .3-1 1.6v2.2l.5 .5h9.2a.71 .71 0 0 0 .6-.8M276.9 104.3l.2 .5M276.9 104.6l.1 1.9-.3 .4M277.1 102.5h-.7v.2h-14.5M277.1 107l-.6 .5M308.3 102.5h25.4M308.3 103.8h25.4M66.2 125.8a2.35 2.35 0 0 1 2.1-.3h6.9a2.29 2.29 0 0 1 2 .3M66.2 125.8h11M66.2 131.1a2.35 2.35 0 0 0 2.1 .4h6.9a2.29 2.29 0 0 0 2-.4M66.2 131.1h11M66.2 125.8v5.3"/>
<path d="M68.7 125.2h3M68.7 122.5v.1M68.7 125.2v.3M69.4 125h.1M69.4 125l-.7 .2M69.4 123v.1M69.4 124v.1M69.4 125l2.3 .2M69.4 123.1l-.7 .4M69.4 124.1l-.7 .4M69.6 122.5l-.9 .1 .7 .4M73.9 125.2h.8"/>
<path d="M74.1 122.6v-.1l-4.7 .5M74.1 124.5l-4.7 .5M74.1 122.6l-4.7 .5M74.1 123.6l-4.7 .5M74.1 124.6l-3.8 .4M74.1 123.5v.1M74.1 124.5v.1M74.1 122.6l.6 .4M74.1 123.6l.6 .4M74.1 124.6l.6 .4M74.6 125.2h-.7M74.6 125.2h.1"/>
<path d="M74.7 123.1l-.7 .4-4.6 .5M74.7 123l-5.6 .4-.4 .2M74.7 124l-5.6 .4-.4 .2M74.7 125l-3 .2M74.7 124.1l-.6 .4M74.7 125.1l-.1 .1M74.7 123v.1l-.4 .1-5.6 .4 .7 .4M74.7 124.1l-6 .5 .7 .4M74.7 125.1l-.8 .1M74.7 124v.1M74.7 125v.1M74.7 125.2v.3"/>
<path d="M77.2 125.8v5.3M105.3 125.8l.3-.3h10.3l.3 .3M105.3 125.8h10.9M105.3 131.1l.3 .4h10.3l.3-.4M105.3 131.1h10.9M105.3 125.8v5.3M107.8 125.2h2.9M107.8 122.5v.1M107.8 123.5v.1M107.8 124.5v.1M107.8 125.2v.3M107.8 124.6l.6 .4"/>
<path d="M107.8 122.6l.6 .4M108.4 125h.1M108.4 125l-.6 .2M108.4 123v.1M108.4 124v.1M108.4 125l2.3 .2M108.6 122.5l-.8 .1M112.9 125.2h.8M113.1 122.6v-.1l-4.7 .5M113.1 124.5l-4.7 .5M113.1 122.6l-4.4 .4-.9 .5M113.1 123.6l-4.4 .4-.9 .5"/>
<path d="M113.1 124.6l-3.8 .4M113.1 123.5v.1M113.1 124.5v.1M113.1 122.6l.6 .4M113.1 123.6l.6 .4M113.1 124.6l.6 .4M113.6 125.2h-.7M113.6 125.2h.1M113.7 123.1l-.7 .4-4.6 .5M113.7 123v.1l-.4 .1-5.5 .4 .6 .4M113.7 124.1l-5.9 .5M113.7 125.1l-.8 .1"/>
<path d="M113.7 123l-5.9 .5M113.7 124l-5.9 .5M113.7 125l-3 .2M113.7 124v.1M113.7 125v.1M113.7 125.2v.3M113.7 124.1l-.6 .4M113.7 125.1l-.1 .1M116.2 125.8v5.3M144.3 125.8l.3-.3h8.6a2.35 2.35 0 0 1 2.1 .3M144.3 125.8h11M144.3 131.1l.3 .4h8.6a2.35 2.35 0 0 0 2.1-.4"/>
<path d="M144.3 131.1h11M144.3 125.8v5.3M146.7 125.2h3.1M146.7 122.5v.1M146.7 123.5v.1M146.7 124.5v.1M146.7 125.2v.3M146.7 124.6l.7 .4M146.7 122.6l.7 .4M147.4 125h.1M147.4 125l-.7 .2M147.4 123v.1"/>
<path d="M147.4 124v.1M147.4 123.1l-.7 .4M147.4 124.1l-.7 .4M147.4 125l2.4 .2M147.6 122.5l-.9 .1M151.9 125.2h.8M152.1 122.6v-.1l-4.7 .5M152.1 122.6l-4.7 .5M152.1 123.6l-4.7 .5M152.1 124.6l-3.8 .4M152.1 123.5v.1M152.1 124.5v.1"/>
<path d="M152.1 122.6l.6 .4M152.1 123.6l.6 .4M152.1 124.6l.6 .4M152.6 125.2h-.7M152.6 125.2h.1M152.7 123.1l-.9 .5-4.4 .4M152.7 124.1l-.8 .5-4.5 .4M152.7 123v.1l-.4 .1-5.6 .4 .7 .4M152.7 124.1l-6 .5M152.7 125.1l-.8 .1M152.7 123l-6 .5M152.7 124l-6 .5"/>
<path d="M152.7 125l-2.9 .2M152.7 124v.1M152.7 125v.1M152.7 125.2v.3M152.7 125.1l-.1 .1M155.3 125.8v5.3M254.7 125.8a2.35 2.35 0 0 1 2.1-.3h6.9a2.29 2.29 0 0 1 2 .3M254.7 125.8h11M254.7 131.1a2.35 2.35 0 0 0 2.1 .4h6.9a2.29 2.29 0 0 0 2-.4M254.7 131.1h11M254.7 125.8v5.3M257.2 125.2h6"/>
<path d="M257.2 123l6-.5-.4 .2-5.6 .4 .7 .4M257.2 123v.1M257.2 124v.1M257.2 125v.1M257.2 125.2v.3M257.2 125.1l.1 .1M257.2 124.1l.7 .4M257.3 125.2h-.1M257.9 122.5v.1M257.9 123.5v.1M257.9 124.5v.1M258.6 122.5l-.7 .1-.7 .4"/>
<path d="M262.6 123l-4.7 .5M262.6 124l-4.7 .5M262.6 123.1l-4.5 .4-.9 .5M262.6 124.1l-4.5 .4-.9 .5M262.6 123.1l.6 .4-6 .5M262.6 124.1l.6 .4-6 .5M262.6 123v.1M262.6 124v.1M262.6 125l.6 .2M263.2 124.6l-.7 .4-5.2 .2M263.2 122.6l-.6 .4M263.2 123.6l-.6 .4"/>
<path d="M263.2 123.5v.1l-.5 .1-5.5 .4M263.2 124.5v.1l-.5 .1-5.5 .4M263.2 125.2v.3M265.7 125.8v5.3M293.7 125.8l.3-.3h10.4l.3 .3M293.7 125.8h11M293.7 131.1l.3 .4h10.4l.3-.4M293.7 131.1h11M293.7 125.8v5.3M296.2 125.2h6M296.2 123l6-.5-.6 .5M296.2 123v.1"/>
<path d="M296.2 124v.1M296.2 125v.1M296.2 125.2v.3M296.2 125.1l.1 .1M296.2 124.1l.7 .4M296.4 125.2h-.2M296.9 122.5v.1M296.9 123.5v.1M296.9 124.5v.1M296.9 122.6l-.7 .4M296.9 123.6l-.7 .4M296.9 124.6l-.7 .4"/>
<path d="M297.5 122.5l-.6 .1M301.6 123l-4.7 .5M301.6 124l-4.7 .5M301.6 123.1l-4.7 .5M301.6 124.1l-4.7 .5M301.6 123v.1M301.6 124v.1M301.6 123.1l.6 .4M301.6 124.1l.6 .4M301.6 125l-5.2 .2M301.6 125l.6 .2M302.2 122.6l-6 .5 .7 .4"/>
<path d="M302.2 123.5v.1l-.6 .1-5.4 .4M302.2 124.6l-6 .5M302.2 123.5l-6 .5M302.2 124.5l-6 .5M302.2 124.5v.1M302.2 125.2v.3M302.2 123.6l-.6 .4M302.2 124.6l-.6 .4M304.7 125.8v5.3M332.7 125.8l.4-.3h10.3l.3 .3M332.7 125.8h11M332.7 131.1l.4 .4h10.3l.3-.4"/>
<path d="M332.7 131.1h11M332.7 125.8v5.3M335.2 125.2h6M335.2 123l6-.5-.6 .5M335.2 123v.1M335.2 124v.1M335.2 125v.1M335.2 125.2v.3M335.2 125.1l.1 .1M335.2 124.1l.7 .4M335.4 125.2h-.2M335.9 122.5v.1"/>
<path d="M335.9 123.5v.1M335.9 124.5v.1M335.9 122.6l-.7 .4M335.9 123.6l-.7 .4M335.9 124.6l-.7 .4M336.5 122.5l-.6 .1M340.6 123l-4.7 .5M340.6 124l-4.7 .5M340.6 123.1l-4.7 .5M340.6 124.1l-4.7 .5M340.6 123v.1M340.6 124v.1"/>
<path d="M340.6 123.1l.6 .4M340.6 124.1l.6 .4M340.6 125l-5.2 .2M340.6 125l.6 .2M341.2 122.6l-6 .5 .7 .4M341.2 123.5l-.3 .2-5.7 .4M341.2 124.6l-6 .5M341.2 123.5l-6 .5M341.2 124.5l-6 .5M341.2 124.5v.1M341.2 125.2v.3M341.2 123.6l-.6 .4"/>
<path d="M341.2 124.6l-.6 .4M343.7 125.8v5.3"/>
<circle cx="50.9" cy="34.5" r="5.2"/>
<circle cx="50.9" cy="34.5" r="5.5"/>
<circle cx="359.1" cy="34.5" r="2.85"/>
<circle cx="49.2" cy="54.5" r="5.2"/>
<circle cx="49.2" cy="54.5" r="5.5"/>
<circle cx="171.2" cy="54.5" r="6.5"/>
<circle cx="171.2" cy="54.5" r="5.2"/>
<circle cx="171.2" cy="54.5" r="5.5"/>
<circle cx="238.7" cy="54.5" r="5.2"/>
<circle cx="238.7" cy="54.5" r="5.5"/>
<circle cx="360.8" cy="54.5" r="1.85"/>
<circle cx="360.8" cy="54.5" r="2.85"/>
<circle cx="171.2" cy="80.5" r="5.2"/>
<circle cx="171.2" cy="80.5" r="5.5"/>
<circle cx="238.7" cy="80.5" r="5.2"/>
<circle cx="238.7" cy="80.5" r="5.5"/>
</g>
<g fill="#000" stroke="#000" stroke-width=".25">
<circle cx="97.8" cy="72.5" r=".24"/>
<circle cx="108.6" cy="72.1" r=".24"/>
<circle cx="108.9" cy="71.5" r=".24"/>
<circle cx="113.2" cy="73.8" r=".24"/>
<circle cx="114.9" cy="72" r=".24"/>
<circle cx="296.9" cy="122.5" r=".24"/>
<circle cx="335.9" cy="122.5" r=".24"/>
</g>
<!-- layer: Visible Narrow -->
<g fill="none" stroke="#000" stroke-width=".25">
<path d="M251.6 48.2v12.6M299.2 48.6v21.1M311.8 48.6v21.1M312.9 48.6v21.1M352.8 54.5h1M356.2 59.8l-.5 .7M245.7 61.5h5.5M251.6 61.9v8.5M251.7 71.4v10.4M290.1 71.4v10.4M338.3 68.9h7.7M341.2 64.9l-.7 .4"/>
<path d="M354.8 70.9v.7M354.8 77.1v11.1M361.8 64.5l-.6 .7M361.8 66.1v4.5M361.8 71.5v11.3M362.4 65.1l-.6 .7M247.3 87.3h10.8M258.7 88.6v22.6M259 87.3h4.1M262.3 82.3l-1.4 .4-1.1 1-.8 1.6-.3 2M266.7 92.5h.5M266.7 90.9h.5"/>
<path d="M266.9 90.3l.2 .1M267 90.9v1.5M267 92.5l.4 .6M267 92.5l.4 .5M267.1 90.5l-.1 .3M267.1 90.4v.1M267.1 90.5l.2 .1M267.3 90.9h1.6M267.4 90.6h1.6M267.4 93l-.1 .3M267.5 92.5h4.3M267.5 92.9l-.1 .1"/>
<path d="M267.8 89l.2 .1M267.8 93.1h8.3M267.9 93h8.3M267.9 89.2l-.8 1.2M268 89.1h.1M268.1 89.2h.1M268.2 88.7l.1 .2M268.3 88.9l-.3 .2M268.3 88.9l-.2 .2M268.3 89.2h1.6M268.3 89l.1 .1M268.7 88.9h6.6"/>
<path d="M268.7 89h6.7M269.1 88.5h.1M270 88.5h1.5M270.7 91h.4M271.1 92h3.9M271.2 90.9h.6M271.2 90.6h.7M271.4 91.5h.4M272.1 89.2h.7M272.3 91.5h.5M273.2 91.5h.5M274.2 91.5h.4"/>
<path d="M275.1 91.5h.4M275.6 88.7l.1 .2M275.7 88.9v.1M275.7 89l.1 .1M275.7 92.2h1.2M275.7 88.9l.3 .2M275.7 89l.3 .1M275.9 91.4h1M276 89.2h.1M276 89.1h.1M276 89v.1M276 89.2l.9 1.2"/>
<path d="M276.2 88.8h.9M276.6 93.1l-.1 .2M276.6 93v.1M276.7 92.9l-.1 .1M276.9 90.5v.1M276.9 90.4v.1M276.9 90.5l.2 .4M276.9 90.3v.1M277 92.5h.1M277 92.5l-.4 .6M277 90.9v1.5M277 90.2h.1"/>
<path d="M308.3 84.7h1.9M310.3 84.8v.5M310.7 82.3l-.2 .5-.2 1.7M311.4 84.7h19.2M331.4 82.3l.2 .5 .1 1.7M331.7 84.8v.5M331.9 84.7h1.8M259.4 113v9M266.7 106.5h.5M266.7 104.8h.5M266.9 104.3l.2 .1M267 104.9v1.5"/>
<path d="M267 106.5l.4 .6M267 106.5l.4 .5M267.1 104.4l-.1 .4M267.1 104.4l.2 .2M267.1 104.5l-.1 .3M267.3 106.5h.6M267.3 104.8h.6M267.3 104.6h.7M267.4 107.1l-.1 .2M267.4 107v.1M267.5 106.9l-.1 .1M267.8 103l.2 .1"/>
<path d="M267.9 103.2l-.8 1.2M268.2 102.8l.1 .1M268.3 103.3h.8M268.3 102.9l-.3 .2 .2 .1M268.3 102.9l-.2 .2M268.3 103l.1 .1M268.7 102.9l6.7 .1M275.6 102.8l.1 .1M275.7 102.9v.1M275.7 103l.1 .1M275.7 102.9l.3 .2M275.7 103l.3 .1"/>
<path d="M276 103.2l.9 1.2M276 103.1h.1M276 103v.1M276.2 107l-8.4 .1M276.2 102.8h.9M276.6 107.1l-.1 .2M276.6 107v.1M276.7 106.9l-.1 .1M276.9 104.5v.1M276.9 104.4v.1M276.9 104.3v.1M276.9 104.5l.1 .3z"/>
<path d="M277 106.5h.1M277 104.8h.1M277 106.5l-.4 .6M277 104.9v1.5M277 104.1h.1"/>
</g>
<!-- layer: Border -->
<g fill="none" stroke="#000" stroke-width=".25">
<path d="M15 .1h-15v15M20 10.1h390v276.9h-390zM65 5.1v5M115 5.1v5M165 5.1v5M215 5.1v10M265 5.1v5M315 5.1v5M365 5.1v5M405 .1h15v15M15 52.9h5M410 52.9h5"/>
<path d="M15 100.7h5M410 100.7h5M15 148.6h10M405 148.6h10M15 196.4h5M410 196.4h5M15 244.2h5M410 244.2h5M0 282.1v14.9h15M65 287v5M115 287v5M165 287v5"/>
<path d="M215 282.1v9.9M265 287v5M315 287v5M365 287v5M420 282.1v14.9h-15"/>
</g>
<!-- layer: TitleBlock -->
<path d="M230 240.1h180v46.9h-180zM230 250h180M254 240.1v9.9M288 240.1v46.9M349 240.1v46.9M288 260.1h122M349 277.1h61M359 277.1v9.9M395 277.1v9.9" fill="none" stroke="#000" stroke-width=".36"/>
<!-- layer: Annotations -->
<path d="M113.1 92.5l-.2 3.6-1.1-.3zM137.9 99.5l1.4 3.3-1.2 .2zM320 99l-.6 3.5-1.1-.3z" fill="#000" stroke="#000" stroke-width=".25"/>
<path d="M112.3 96l-13.1 60.4h-32.5M138.7 102.9l12.2 54h29.6M318.9 102.3l-15.6 48.7h-30.3" fill="none" stroke="#000" stroke-width=".25"/>
<!-- layer: Sketch1 -->
<path d="M45 157.1v19.9h80v-19.9h-80h16v19.9M61 157.1h16v19.9M77 157.1h16v19.9M93 157.1h16v19.9M151 159.1h60v29.9h-60zM151 159.1h20v29.9M171 159.1h20v29.9M151 174.1h60" fill="none" stroke="#000" stroke-width=".36"/>
<!-- layer: Sketch2 -->
<path d="M260.7 152h60v20h-60zM275.7 152v20M290.7 152v20M305.7 152v20" fill="none" stroke="#000" stroke-width=".36"/>
<use href="#words"/>
</svg>
